VERSION 5.7 ;
  NOWIREEXTENSIONATPIN ON ;
  DIVIDERCHAR "/" ;
  BUSBITCHARS "[]" ;
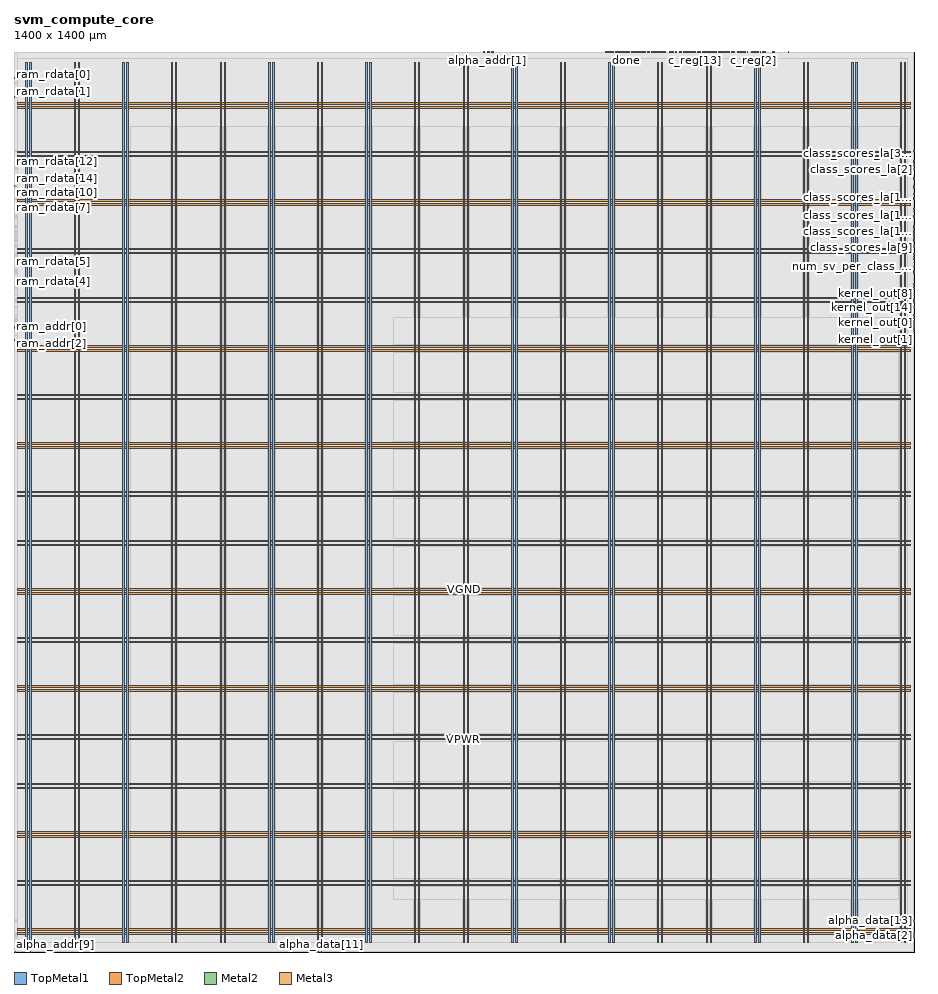
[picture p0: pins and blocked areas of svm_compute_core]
MACRO svm_compute_core
  CLASS BLOCK ;
  FOREIGN svm_compute_core ;
  ORIGIN 0.000 0.000 ;
  SIZE 1400.000 BY 1400.000 ;
  PIN VGND
    DIRECTION INOUT ;
    USE GROUND ;
    PORT
      LAYER TopMetal1 ;
        RECT 24.460 14.490 26.660 1384.110 ;
    END
    PORT
      LAYER TopMetal1 ;
        RECT 100.060 14.490 102.260 1384.110 ;
    END
    PORT
      LAYER TopMetal1 ;
        RECT 175.660 14.490 177.860 1384.110 ;
    END
    PORT
      LAYER TopMetal1 ;
        RECT 251.260 14.490 253.460 1384.110 ;
    END
    PORT
      LAYER TopMetal1 ;
        RECT 326.860 14.490 329.060 1384.110 ;
    END
    PORT
      LAYER TopMetal1 ;
        RECT 402.460 14.490 404.660 1384.110 ;
    END
    PORT
      LAYER TopMetal1 ;
        RECT 478.060 14.490 480.260 1384.110 ;
    END
    PORT
      LAYER TopMetal1 ;
        RECT 553.660 14.490 555.860 1384.110 ;
    END
    PORT
      LAYER TopMetal1 ;
        RECT 629.260 14.490 631.460 1384.110 ;
    END
    PORT
      LAYER TopMetal1 ;
        RECT 704.860 14.490 707.060 1384.110 ;
    END
    PORT
      LAYER TopMetal1 ;
        RECT 780.460 14.490 782.660 1384.110 ;
    END
    PORT
      LAYER TopMetal1 ;
        RECT 856.060 14.490 858.260 1384.110 ;
    END
    PORT
      LAYER TopMetal1 ;
        RECT 931.660 14.490 933.860 1384.110 ;
    END
    PORT
      LAYER TopMetal1 ;
        RECT 1007.260 14.490 1009.460 1384.110 ;
    END
    PORT
      LAYER TopMetal1 ;
        RECT 1082.860 14.490 1085.060 1384.110 ;
    END
    PORT
      LAYER TopMetal1 ;
        RECT 1158.460 14.490 1160.660 1384.110 ;
    END
    PORT
      LAYER TopMetal1 ;
        RECT 1234.060 14.490 1236.260 1384.110 ;
    END
    PORT
      LAYER TopMetal1 ;
        RECT 1309.660 14.490 1311.860 1384.110 ;
    END
    PORT
      LAYER TopMetal1 ;
        RECT 1385.260 14.490 1387.460 1384.110 ;
    END
    PORT
      LAYER TopMetal2 ;
        RECT 5.760 33.820 1393.920 36.020 ;
    END
    PORT
      LAYER TopMetal2 ;
        RECT 5.760 109.420 1393.920 111.620 ;
    END
    PORT
      LAYER TopMetal2 ;
        RECT 5.760 185.020 1393.920 187.220 ;
    END
    PORT
      LAYER TopMetal2 ;
        RECT 5.760 260.620 1393.920 262.820 ;
    END
    PORT
      LAYER TopMetal2 ;
        RECT 5.760 336.220 1393.920 338.420 ;
    END
    PORT
      LAYER TopMetal2 ;
        RECT 5.760 411.820 1393.920 414.020 ;
    END
    PORT
      LAYER TopMetal2 ;
        RECT 5.760 487.420 1393.920 489.620 ;
    END
    PORT
      LAYER TopMetal2 ;
        RECT 5.760 563.020 1393.920 565.220 ;
    END
    PORT
      LAYER TopMetal2 ;
        RECT 5.760 638.620 1393.920 640.820 ;
    END
    PORT
      LAYER TopMetal2 ;
        RECT 5.760 714.220 1393.920 716.420 ;
    END
    PORT
      LAYER TopMetal2 ;
        RECT 5.760 789.820 1393.920 792.020 ;
    END
    PORT
      LAYER TopMetal2 ;
        RECT 5.760 865.420 1393.920 867.620 ;
    END
    PORT
      LAYER TopMetal2 ;
        RECT 5.760 941.020 1393.920 943.220 ;
    END
    PORT
      LAYER TopMetal2 ;
        RECT 5.760 1016.620 1393.920 1018.820 ;
    END
    PORT
      LAYER TopMetal2 ;
        RECT 5.760 1092.220 1393.920 1094.420 ;
    END
    PORT
      LAYER TopMetal2 ;
        RECT 5.760 1167.820 1393.920 1170.020 ;
    END
    PORT
      LAYER TopMetal2 ;
        RECT 5.760 1243.420 1393.920 1245.620 ;
    END
    PORT
      LAYER TopMetal2 ;
        RECT 5.760 1319.020 1393.920 1321.220 ;
    END
  END VGND
  PIN VPWR
    DIRECTION INOUT ;
    USE POWER ;
    PORT
      LAYER TopMetal1 ;
        RECT 18.260 14.900 20.460 1383.700 ;
    END
    PORT
      LAYER TopMetal1 ;
        RECT 93.860 14.900 96.060 1383.700 ;
    END
    PORT
      LAYER TopMetal1 ;
        RECT 169.460 14.900 171.660 1383.700 ;
    END
    PORT
      LAYER TopMetal1 ;
        RECT 245.060 14.900 247.260 1383.700 ;
    END
    PORT
      LAYER TopMetal1 ;
        RECT 320.660 14.900 322.860 1383.700 ;
    END
    PORT
      LAYER TopMetal1 ;
        RECT 396.260 14.900 398.460 1383.700 ;
    END
    PORT
      LAYER TopMetal1 ;
        RECT 471.860 14.900 474.060 1383.700 ;
    END
    PORT
      LAYER TopMetal1 ;
        RECT 547.460 14.900 549.660 1383.700 ;
    END
    PORT
      LAYER TopMetal1 ;
        RECT 623.060 14.900 625.260 1383.700 ;
    END
    PORT
      LAYER TopMetal1 ;
        RECT 698.660 14.900 700.860 1383.700 ;
    END
    PORT
      LAYER TopMetal1 ;
        RECT 774.260 14.900 776.460 1383.700 ;
    END
    PORT
      LAYER TopMetal1 ;
        RECT 849.860 14.900 852.060 1383.700 ;
    END
    PORT
      LAYER TopMetal1 ;
        RECT 925.460 14.900 927.660 1383.700 ;
    END
    PORT
      LAYER TopMetal1 ;
        RECT 1001.060 14.900 1003.260 1383.700 ;
    END
    PORT
      LAYER TopMetal1 ;
        RECT 1076.660 14.900 1078.860 1383.700 ;
    END
    PORT
      LAYER TopMetal1 ;
        RECT 1152.260 14.900 1154.460 1383.700 ;
    END
    PORT
      LAYER TopMetal1 ;
        RECT 1227.860 14.900 1230.060 1383.700 ;
    END
    PORT
      LAYER TopMetal1 ;
        RECT 1303.460 14.900 1305.660 1383.700 ;
    END
    PORT
      LAYER TopMetal1 ;
        RECT 1379.060 14.900 1381.260 1383.700 ;
    END
    PORT
      LAYER TopMetal2 ;
        RECT 5.760 27.620 1393.920 29.820 ;
    END
    PORT
      LAYER TopMetal2 ;
        RECT 5.760 103.220 1393.920 105.420 ;
    END
    PORT
      LAYER TopMetal2 ;
        RECT 5.760 178.820 1393.920 181.020 ;
    END
    PORT
      LAYER TopMetal2 ;
        RECT 5.760 254.420 1393.920 256.620 ;
    END
    PORT
      LAYER TopMetal2 ;
        RECT 5.760 330.020 1393.920 332.220 ;
    END
    PORT
      LAYER TopMetal2 ;
        RECT 5.760 405.620 1393.920 407.820 ;
    END
    PORT
      LAYER TopMetal2 ;
        RECT 5.760 481.220 1393.920 483.420 ;
    END
    PORT
      LAYER TopMetal2 ;
        RECT 5.760 556.820 1393.920 559.020 ;
    END
    PORT
      LAYER TopMetal2 ;
        RECT 5.760 632.420 1393.920 634.620 ;
    END
    PORT
      LAYER TopMetal2 ;
        RECT 5.760 708.020 1393.920 710.220 ;
    END
    PORT
      LAYER TopMetal2 ;
        RECT 5.760 783.620 1393.920 785.820 ;
    END
    PORT
      LAYER TopMetal2 ;
        RECT 5.760 859.220 1393.920 861.420 ;
    END
    PORT
      LAYER TopMetal2 ;
        RECT 5.760 934.820 1393.920 937.020 ;
    END
    PORT
      LAYER TopMetal2 ;
        RECT 5.760 1010.420 1393.920 1012.620 ;
    END
    PORT
      LAYER TopMetal2 ;
        RECT 5.760 1086.020 1393.920 1088.220 ;
    END
    PORT
      LAYER TopMetal2 ;
        RECT 5.760 1161.620 1393.920 1163.820 ;
    END
    PORT
      LAYER TopMetal2 ;
        RECT 5.760 1237.220 1393.920 1239.420 ;
    END
    PORT
      LAYER TopMetal2 ;
        RECT 5.760 1312.820 1393.920 1315.020 ;
    END
  END VPWR
  PIN alpha_addr[0]
    DIRECTION INPUT ;
    USE SIGNAL ;
    ANTENNAGATEAREA 0.109200 ;
    PORT
      LAYER Metal2 ;
        RECT 737.560 1399.600 737.960 1400.000 ;
    END
  END alpha_addr[0]
  PIN alpha_addr[1]
    DIRECTION INPUT ;
    USE SIGNAL ;
    ANTENNAGATEAREA 0.109200 ;
    PORT
      LAYER Metal2 ;
        RECT 736.600 1399.600 737.000 1400.000 ;
    END
  END alpha_addr[1]
  PIN alpha_addr[2]
    DIRECTION INPUT ;
    USE SIGNAL ;
    ANTENNAGATEAREA 0.109200 ;
    PORT
      LAYER Metal2 ;
        RECT 745.240 1399.600 745.640 1400.000 ;
    END
  END alpha_addr[2]
  PIN alpha_addr[3]
    DIRECTION INPUT ;
    USE SIGNAL ;
    ANTENNAGATEAREA 0.109200 ;
    PORT
      LAYER Metal2 ;
        RECT 746.200 1399.600 746.600 1400.000 ;
    END
  END alpha_addr[3]
  PIN alpha_addr[4]
    DIRECTION INPUT ;
    USE SIGNAL ;
    ANTENNAGATEAREA 0.109200 ;
    PORT
      LAYER Metal2 ;
        RECT 738.520 1399.600 738.920 1400.000 ;
    END
  END alpha_addr[4]
  PIN alpha_addr[5]
    DIRECTION INPUT ;
    USE SIGNAL ;
    ANTENNAGATEAREA 0.109200 ;
    PORT
      LAYER Metal2 ;
        RECT 739.480 1399.600 739.880 1400.000 ;
    END
  END alpha_addr[5]
  PIN alpha_addr[6]
    DIRECTION INPUT ;
    USE SIGNAL ;
    ANTENNAGATEAREA 0.109200 ;
    PORT
      LAYER Metal2 ;
        RECT 744.280 1399.600 744.680 1400.000 ;
    END
  END alpha_addr[6]
  PIN alpha_addr[7]
    DIRECTION INPUT ;
    USE SIGNAL ;
    ANTENNAGATEAREA 0.109200 ;
    PORT
      LAYER Metal2 ;
        RECT 743.320 1399.600 743.720 1400.000 ;
    END
  END alpha_addr[7]
  PIN alpha_addr[8]
    DIRECTION INPUT ;
    USE SIGNAL ;
    ANTENNAGATEAREA 0.109200 ;
    PORT
      LAYER Metal2 ;
        RECT 730.840 1399.600 731.240 1400.000 ;
    END
  END alpha_addr[8]
  PIN alpha_addr[9]
    DIRECTION INPUT ;
    USE SIGNAL ;
    PORT
      LAYER Metal2 ;
        RECT 2.200 0.000 2.600 0.400 ;
    END
  END alpha_addr[9]
  PIN alpha_data[0]
    DIRECTION INPUT ;
    USE SIGNAL ;
    ANTENNAGATEAREA 0.109200 ;
    PORT
      LAYER Metal2 ;
        RECT 996.760 1399.600 997.160 1400.000 ;
    END
  END alpha_data[0]
  PIN alpha_data[10]
    DIRECTION INPUT ;
    USE SIGNAL ;
    ANTENNAGATEAREA 0.109200 ;
    PORT
      LAYER Metal2 ;
        RECT 1012.120 1399.600 1012.520 1400.000 ;
    END
  END alpha_data[10]
  PIN alpha_data[11]
    DIRECTION INPUT ;
    USE SIGNAL ;
    ANTENNAGATEAREA 0.109200 ;
    PORT
      LAYER Metal2 ;
        RECT 478.360 0.000 478.760 0.400 ;
    END
  END alpha_data[11]
  PIN alpha_data[12]
    DIRECTION INPUT ;
    USE SIGNAL ;
    ANTENNAGATEAREA 0.109200 ;
    PORT
      LAYER Metal2 ;
        RECT 472.600 0.000 473.000 0.400 ;
    END
  END alpha_data[12]
  PIN alpha_data[13]
    DIRECTION INPUT ;
    USE SIGNAL ;
    ANTENNAGATEAREA 0.109200 ;
    PORT
      LAYER Metal3 ;
        RECT 1399.600 48.100 1400.000 48.500 ;
    END
  END alpha_data[13]
  PIN alpha_data[14]
    DIRECTION INPUT ;
    USE SIGNAL ;
    ANTENNAGATEAREA 0.109200 ;
    PORT
      LAYER Metal3 ;
        RECT 1399.600 22.900 1400.000 23.300 ;
    END
  END alpha_data[14]
  PIN alpha_data[15]
    DIRECTION INPUT ;
    USE SIGNAL ;
    ANTENNAGATEAREA 0.109200 ;
    PORT
      LAYER Metal3 ;
        RECT 1399.600 23.740 1400.000 24.140 ;
    END
  END alpha_data[15]
  PIN alpha_data[1]
    DIRECTION INPUT ;
    USE SIGNAL ;
    ANTENNAGATEAREA 0.109200 ;
    PORT
      LAYER Metal3 ;
        RECT 1399.600 24.580 1400.000 24.980 ;
    END
  END alpha_data[1]
  PIN alpha_data[2]
    DIRECTION INPUT ;
    USE SIGNAL ;
    ANTENNAGATEAREA 0.109200 ;
    PORT
      LAYER Metal3 ;
        RECT 1399.600 25.420 1400.000 25.820 ;
    END
  END alpha_data[2]
  PIN alpha_data[3]
    DIRECTION INPUT ;
    USE SIGNAL ;
    ANTENNAGATEAREA 0.109200 ;
    PORT
      LAYER Metal3 ;
        RECT 1399.600 26.260 1400.000 26.660 ;
    END
  END alpha_data[3]
  PIN alpha_data[4]
    DIRECTION INPUT ;
    USE SIGNAL ;
    ANTENNAGATEAREA 0.109200 ;
    PORT
      LAYER Metal2 ;
        RECT 1205.080 1399.600 1205.480 1400.000 ;
    END
  END alpha_data[4]
  PIN alpha_data[5]
    DIRECTION INPUT ;
    USE SIGNAL ;
    ANTENNAGATEAREA 0.109200 ;
    PORT
      LAYER Metal3 ;
        RECT 1399.600 27.100 1400.000 27.500 ;
    END
  END alpha_data[5]
  PIN alpha_data[6]
    DIRECTION INPUT ;
    USE SIGNAL ;
    ANTENNAGATEAREA 0.109200 ;
    PORT
      LAYER Metal3 ;
        RECT 1399.600 27.940 1400.000 28.340 ;
    END
  END alpha_data[6]
  PIN alpha_data[7]
    DIRECTION INPUT ;
    USE SIGNAL ;
    ANTENNAGATEAREA 0.109200 ;
    PORT
      LAYER Metal3 ;
        RECT 1399.600 49.780 1400.000 50.180 ;
    END
  END alpha_data[7]
  PIN alpha_data[8]
    DIRECTION INPUT ;
    USE SIGNAL ;
    ANTENNAGATEAREA 0.109200 ;
    PORT
      LAYER Metal3 ;
        RECT 1399.600 48.940 1400.000 49.340 ;
    END
  END alpha_data[8]
  PIN alpha_data[9]
    DIRECTION INPUT ;
    USE SIGNAL ;
    ANTENNAGATEAREA 0.109200 ;
    PORT
      LAYER Metal3 ;
        RECT 1399.600 28.780 1400.000 29.180 ;
    END
  END alpha_data[9]
  PIN alpha_write_en
    DIRECTION INPUT ;
    USE SIGNAL ;
    ANTENNAGATEAREA 0.109200 ;
    PORT
      LAYER Metal2 ;
        RECT 729.880 1399.600 730.280 1400.000 ;
    END
  END alpha_write_en
  PIN c_reg[0]
    DIRECTION OUTPUT ;
    USE SIGNAL ;
    ANTENNADIFFAREA 0.708600 ;
    PORT
      LAYER Metal2 ;
        RECT 1133.080 1399.600 1133.480 1400.000 ;
    END
  END c_reg[0]
  PIN c_reg[10]
    DIRECTION OUTPUT ;
    USE SIGNAL ;
    ANTENNADIFFAREA 0.708600 ;
    PORT
      LAYER Metal2 ;
        RECT 1126.360 1399.600 1126.760 1400.000 ;
    END
  END c_reg[10]
  PIN c_reg[11]
    DIRECTION OUTPUT ;
    USE SIGNAL ;
    ANTENNADIFFAREA 0.708600 ;
    PORT
      LAYER Metal2 ;
        RECT 1102.360 1399.600 1102.760 1400.000 ;
    END
  END c_reg[11]
  PIN c_reg[12]
    DIRECTION OUTPUT ;
    USE SIGNAL ;
    ANTENNADIFFAREA 0.708600 ;
    PORT
      LAYER Metal2 ;
        RECT 1091.800 1399.600 1092.200 1400.000 ;
    END
  END c_reg[12]
  PIN c_reg[13]
    DIRECTION OUTPUT ;
    USE SIGNAL ;
    ANTENNADIFFAREA 0.708600 ;
    PORT
      LAYER Metal2 ;
        RECT 1059.160 1399.600 1059.560 1400.000 ;
    END
  END c_reg[13]
  PIN c_reg[14]
    DIRECTION OUTPUT ;
    USE SIGNAL ;
    ANTENNADIFFAREA 0.708600 ;
    PORT
      LAYER Metal2 ;
        RECT 1054.360 1399.600 1054.760 1400.000 ;
    END
  END c_reg[14]
  PIN c_reg[15]
    DIRECTION OUTPUT ;
    USE SIGNAL ;
    ANTENNADIFFAREA 0.708600 ;
    PORT
      LAYER Metal2 ;
        RECT 1078.360 1399.600 1078.760 1400.000 ;
    END
  END c_reg[15]
  PIN c_reg[1]
    DIRECTION OUTPUT ;
    USE SIGNAL ;
    ANTENNADIFFAREA 0.708600 ;
    PORT
      LAYER Metal2 ;
        RECT 1134.040 1399.600 1134.440 1400.000 ;
    END
  END c_reg[1]
  PIN c_reg[2]
    DIRECTION OUTPUT ;
    USE SIGNAL ;
    ANTENNADIFFAREA 0.708600 ;
    PORT
      LAYER Metal2 ;
        RECT 1149.400 1399.600 1149.800 1400.000 ;
    END
  END c_reg[2]
  PIN c_reg[3]
    DIRECTION OUTPUT ;
    USE SIGNAL ;
    ANTENNADIFFAREA 0.708600 ;
    PORT
      LAYER Metal2 ;
        RECT 1136.920 1399.600 1137.320 1400.000 ;
    END
  END c_reg[3]
  PIN c_reg[4]
    DIRECTION OUTPUT ;
    USE SIGNAL ;
    ANTENNADIFFAREA 0.708600 ;
    PORT
      LAYER Metal2 ;
        RECT 1154.200 1399.600 1154.600 1400.000 ;
    END
  END c_reg[4]
  PIN c_reg[5]
    DIRECTION OUTPUT ;
    USE SIGNAL ;
    ANTENNADIFFAREA 0.708600 ;
    PORT
      LAYER Metal2 ;
        RECT 1156.120 1399.600 1156.520 1400.000 ;
    END
  END c_reg[5]
  PIN c_reg[6]
    DIRECTION OUTPUT ;
    USE SIGNAL ;
    ANTENNADIFFAREA 0.708600 ;
    PORT
      LAYER Metal2 ;
        RECT 1155.160 1399.600 1155.560 1400.000 ;
    END
  END c_reg[6]
  PIN c_reg[7]
    DIRECTION OUTPUT ;
    USE SIGNAL ;
    ANTENNADIFFAREA 0.708600 ;
    PORT
      LAYER Metal2 ;
        RECT 1148.440 1399.600 1148.840 1400.000 ;
    END
  END c_reg[7]
  PIN c_reg[8]
    DIRECTION OUTPUT ;
    USE SIGNAL ;
    ANTENNADIFFAREA 0.708600 ;
    PORT
      LAYER Metal2 ;
        RECT 1098.520 1399.600 1098.920 1400.000 ;
    END
  END c_reg[8]
  PIN c_reg[9]
    DIRECTION OUTPUT ;
    USE SIGNAL ;
    ANTENNADIFFAREA 0.708600 ;
    PORT
      LAYER Metal2 ;
        RECT 1119.640 1399.600 1120.040 1400.000 ;
    END
  END c_reg[9]
  PIN class_out[0]
    DIRECTION OUTPUT ;
    USE SIGNAL ;
    ANTENNADIFFAREA 0.708600 ;
    PORT
      LAYER Metal2 ;
        RECT 1111.960 1399.600 1112.360 1400.000 ;
    END
  END class_out[0]
  PIN class_out[1]
    DIRECTION OUTPUT ;
    USE SIGNAL ;
    ANTENNADIFFAREA 0.708600 ;
    PORT
      LAYER Metal2 ;
        RECT 1111.000 1399.600 1111.400 1400.000 ;
    END
  END class_out[1]
  PIN class_out[2]
    DIRECTION OUTPUT ;
    USE SIGNAL ;
    ANTENNADIFFAREA 0.708600 ;
    PORT
      LAYER Metal2 ;
        RECT 1110.040 1399.600 1110.440 1400.000 ;
    END
  END class_out[2]
  PIN class_scores_la[0]
    DIRECTION OUTPUT ;
    USE SIGNAL ;
    ANTENNADIFFAREA 0.708600 ;
    PORT
      LAYER Metal3 ;
        RECT 1399.600 1219.060 1400.000 1219.460 ;
    END
  END class_scores_la[0]
  PIN class_scores_la[100]
    DIRECTION OUTPUT ;
    USE SIGNAL ;
    ANTENNADIFFAREA 0.708600 ;
    PORT
      LAYER Metal3 ;
        RECT 1399.600 1173.700 1400.000 1174.100 ;
    END
  END class_scores_la[100]
  PIN class_scores_la[101]
    DIRECTION OUTPUT ;
    USE SIGNAL ;
    ANTENNADIFFAREA 0.708600 ;
    PORT
      LAYER Metal3 ;
        RECT 1399.600 1156.060 1400.000 1156.460 ;
    END
  END class_scores_la[101]
  PIN class_scores_la[102]
    DIRECTION OUTPUT ;
    USE SIGNAL ;
    ANTENNADIFFAREA 0.708600 ;
    PORT
      LAYER Metal3 ;
        RECT 1399.600 1141.780 1400.000 1142.180 ;
    END
  END class_scores_la[102]
  PIN class_scores_la[103]
    DIRECTION OUTPUT ;
    USE SIGNAL ;
    ANTENNADIFFAREA 0.708600 ;
    PORT
      LAYER Metal3 ;
        RECT 1399.600 1119.940 1400.000 1120.340 ;
    END
  END class_scores_la[103]
  PIN class_scores_la[104]
    DIRECTION OUTPUT ;
    USE SIGNAL ;
    ANTENNADIFFAREA 0.708600 ;
    PORT
      LAYER Metal3 ;
        RECT 1399.600 1145.140 1400.000 1145.540 ;
    END
  END class_scores_la[104]
  PIN class_scores_la[105]
    DIRECTION OUTPUT ;
    USE SIGNAL ;
    ANTENNADIFFAREA 0.708600 ;
    PORT
      LAYER Metal2 ;
        RECT 1164.760 1399.600 1165.160 1400.000 ;
    END
  END class_scores_la[105]
  PIN class_scores_la[106]
    DIRECTION OUTPUT ;
    USE SIGNAL ;
    ANTENNADIFFAREA 0.708600 ;
    PORT
      LAYER Metal2 ;
        RECT 1147.480 1399.600 1147.880 1400.000 ;
    END
  END class_scores_la[106]
  PIN class_scores_la[107]
    DIRECTION OUTPUT ;
    USE SIGNAL ;
    ANTENNADIFFAREA 0.708600 ;
    PORT
      LAYER Metal2 ;
        RECT 1135.960 1399.600 1136.360 1400.000 ;
    END
  END class_scores_la[107]
  PIN class_scores_la[108]
    DIRECTION OUTPUT ;
    USE SIGNAL ;
    ANTENNADIFFAREA 0.708600 ;
    PORT
      LAYER Metal2 ;
        RECT 1117.720 1399.600 1118.120 1400.000 ;
    END
  END class_scores_la[108]
  PIN class_scores_la[109]
    DIRECTION OUTPUT ;
    USE SIGNAL ;
    ANTENNADIFFAREA 0.708600 ;
    PORT
      LAYER Metal2 ;
        RECT 1104.280 1399.600 1104.680 1400.000 ;
    END
  END class_scores_la[109]
  PIN class_scores_la[10]
    DIRECTION OUTPUT ;
    USE SIGNAL ;
    ANTENNADIFFAREA 0.708600 ;
    PORT
      LAYER Metal2 ;
        RECT 1168.600 1399.600 1169.000 1400.000 ;
    END
  END class_scores_la[10]
  PIN class_scores_la[110]
    DIRECTION OUTPUT ;
    USE SIGNAL ;
    ANTENNADIFFAREA 0.708600 ;
    PORT
      LAYER Metal2 ;
        RECT 1099.480 1399.600 1099.880 1400.000 ;
    END
  END class_scores_la[110]
  PIN class_scores_la[111]
    DIRECTION OUTPUT ;
    USE SIGNAL ;
    ANTENNADIFFAREA 0.708600 ;
    PORT
      LAYER Metal2 ;
        RECT 1097.560 1399.600 1097.960 1400.000 ;
    END
  END class_scores_la[111]
  PIN class_scores_la[112]
    DIRECTION OUTPUT ;
    USE SIGNAL ;
    ANTENNADIFFAREA 0.708600 ;
    PORT
      LAYER Metal2 ;
        RECT 1025.560 1399.600 1025.960 1400.000 ;
    END
  END class_scores_la[112]
  PIN class_scores_la[113]
    DIRECTION OUTPUT ;
    USE SIGNAL ;
    ANTENNADIFFAREA 0.708600 ;
    PORT
      LAYER Metal2 ;
        RECT 1011.160 1399.600 1011.560 1400.000 ;
    END
  END class_scores_la[113]
  PIN class_scores_la[114]
    DIRECTION OUTPUT ;
    USE SIGNAL ;
    ANTENNADIFFAREA 0.708600 ;
    PORT
      LAYER Metal2 ;
        RECT 992.920 1399.600 993.320 1400.000 ;
    END
  END class_scores_la[114]
  PIN class_scores_la[115]
    DIRECTION OUTPUT ;
    USE SIGNAL ;
    ANTENNADIFFAREA 0.708600 ;
    PORT
      LAYER Metal2 ;
        RECT 988.120 1399.600 988.520 1400.000 ;
    END
  END class_scores_la[115]
  PIN class_scores_la[116]
    DIRECTION OUTPUT ;
    USE SIGNAL ;
    ANTENNADIFFAREA 0.708600 ;
    PORT
      LAYER Metal2 ;
        RECT 968.920 1399.600 969.320 1400.000 ;
    END
  END class_scores_la[116]
  PIN class_scores_la[117]
    DIRECTION OUTPUT ;
    USE SIGNAL ;
    ANTENNADIFFAREA 0.708600 ;
    PORT
      LAYER Metal2 ;
        RECT 994.840 1399.600 995.240 1400.000 ;
    END
  END class_scores_la[117]
  PIN class_scores_la[118]
    DIRECTION OUTPUT ;
    USE SIGNAL ;
    ANTENNADIFFAREA 0.708600 ;
    PORT
      LAYER Metal2 ;
        RECT 995.800 1399.600 996.200 1400.000 ;
    END
  END class_scores_la[118]
  PIN class_scores_la[119]
    DIRECTION OUTPUT ;
    USE SIGNAL ;
    ANTENNADIFFAREA 0.708600 ;
    PORT
      LAYER Metal2 ;
        RECT 1046.680 1399.600 1047.080 1400.000 ;
    END
  END class_scores_la[119]
  PIN class_scores_la[11]
    DIRECTION OUTPUT ;
    USE SIGNAL ;
    ANTENNADIFFAREA 0.708600 ;
    PORT
      LAYER Metal2 ;
        RECT 1130.200 1399.600 1130.600 1400.000 ;
    END
  END class_scores_la[11]
  PIN class_scores_la[120]
    DIRECTION OUTPUT ;
    USE SIGNAL ;
    ANTENNADIFFAREA 0.708600 ;
    PORT
      LAYER Metal2 ;
        RECT 1006.360 1399.600 1006.760 1400.000 ;
    END
  END class_scores_la[120]
  PIN class_scores_la[121]
    DIRECTION OUTPUT ;
    USE SIGNAL ;
    ANTENNADIFFAREA 0.708600 ;
    PORT
      LAYER Metal2 ;
        RECT 998.680 1399.600 999.080 1400.000 ;
    END
  END class_scores_la[121]
  PIN class_scores_la[122]
    DIRECTION OUTPUT ;
    USE SIGNAL ;
    ANTENNADIFFAREA 0.708600 ;
    PORT
      LAYER Metal2 ;
        RECT 976.600 1399.600 977.000 1400.000 ;
    END
  END class_scores_la[122]
  PIN class_scores_la[123]
    DIRECTION OUTPUT ;
    USE SIGNAL ;
    ANTENNADIFFAREA 0.708600 ;
    PORT
      LAYER Metal2 ;
        RECT 966.040 1399.600 966.440 1400.000 ;
    END
  END class_scores_la[123]
  PIN class_scores_la[124]
    DIRECTION OUTPUT ;
    USE SIGNAL ;
    ANTENNADIFFAREA 0.708600 ;
    PORT
      LAYER Metal2 ;
        RECT 1088.920 1399.600 1089.320 1400.000 ;
    END
  END class_scores_la[124]
  PIN class_scores_la[125]
    DIRECTION OUTPUT ;
    USE SIGNAL ;
    ANTENNADIFFAREA 0.708600 ;
    PORT
      LAYER Metal2 ;
        RECT 1075.480 1399.600 1075.880 1400.000 ;
    END
  END class_scores_la[125]
  PIN class_scores_la[126]
    DIRECTION OUTPUT ;
    USE SIGNAL ;
    ANTENNADIFFAREA 0.708600 ;
    PORT
      LAYER Metal2 ;
        RECT 1077.400 1399.600 1077.800 1400.000 ;
    END
  END class_scores_la[126]
  PIN class_scores_la[127]
    DIRECTION OUTPUT ;
    USE SIGNAL ;
    ANTENNADIFFAREA 0.708600 ;
    PORT
      LAYER Metal2 ;
        RECT 1085.080 1399.600 1085.480 1400.000 ;
    END
  END class_scores_la[127]
  PIN class_scores_la[12]
    DIRECTION OUTPUT ;
    USE SIGNAL ;
    ANTENNADIFFAREA 0.708600 ;
    PORT
      LAYER Metal3 ;
        RECT 1399.600 1104.820 1400.000 1105.220 ;
    END
  END class_scores_la[12]
  PIN class_scores_la[13]
    DIRECTION OUTPUT ;
    USE SIGNAL ;
    ANTENNADIFFAREA 0.708600 ;
    PORT
      LAYER Metal2 ;
        RECT 1100.440 1399.600 1100.840 1400.000 ;
    END
  END class_scores_la[13]
  PIN class_scores_la[14]
    DIRECTION OUTPUT ;
    USE SIGNAL ;
    ANTENNADIFFAREA 0.708600 ;
    PORT
      LAYER Metal2 ;
        RECT 1086.040 1399.600 1086.440 1400.000 ;
    END
  END class_scores_la[14]
  PIN class_scores_la[15]
    DIRECTION OUTPUT ;
    USE SIGNAL ;
    ANTENNADIFFAREA 0.708600 ;
    PORT
      LAYER Metal2 ;
        RECT 1081.240 1399.600 1081.640 1400.000 ;
    END
  END class_scores_la[15]
  PIN class_scores_la[16]
    DIRECTION OUTPUT ;
    USE SIGNAL ;
    ANTENNADIFFAREA 0.708600 ;
    PORT
      LAYER Metal2 ;
        RECT 1055.320 1399.600 1055.720 1400.000 ;
    END
  END class_scores_la[16]
  PIN class_scores_la[17]
    DIRECTION OUTPUT ;
    USE SIGNAL ;
    ANTENNADIFFAREA 0.708600 ;
    PORT
      LAYER Metal2 ;
        RECT 1045.720 1399.600 1046.120 1400.000 ;
    END
  END class_scores_la[17]
  PIN class_scores_la[18]
    DIRECTION OUTPUT ;
    USE SIGNAL ;
    ANTENNADIFFAREA 0.708600 ;
    PORT
      LAYER Metal2 ;
        RECT 1023.640 1399.600 1024.040 1400.000 ;
    END
  END class_scores_la[18]
  PIN class_scores_la[19]
    DIRECTION OUTPUT ;
    USE SIGNAL ;
    ANTENNADIFFAREA 0.708600 ;
    PORT
      LAYER Metal2 ;
        RECT 1009.240 1399.600 1009.640 1400.000 ;
    END
  END class_scores_la[19]
  PIN class_scores_la[1]
    DIRECTION OUTPUT ;
    USE SIGNAL ;
    ANTENNADIFFAREA 0.708600 ;
    PORT
      LAYER Metal3 ;
        RECT 1399.600 1224.100 1400.000 1224.500 ;
    END
  END class_scores_la[1]
  PIN class_scores_la[20]
    DIRECTION OUTPUT ;
    USE SIGNAL ;
    ANTENNADIFFAREA 0.708600 ;
    PORT
      LAYER Metal2 ;
        RECT 969.880 1399.600 970.280 1400.000 ;
    END
  END class_scores_la[20]
  PIN class_scores_la[21]
    DIRECTION OUTPUT ;
    USE SIGNAL ;
    ANTENNADIFFAREA 0.708600 ;
    PORT
      LAYER Metal2 ;
        RECT 981.400 1399.600 981.800 1400.000 ;
    END
  END class_scores_la[21]
  PIN class_scores_la[22]
    DIRECTION OUTPUT ;
    USE SIGNAL ;
    ANTENNADIFFAREA 0.708600 ;
    PORT
      LAYER Metal2 ;
        RECT 1029.400 1399.600 1029.800 1400.000 ;
    END
  END class_scores_la[22]
  PIN class_scores_la[23]
    DIRECTION OUTPUT ;
    USE SIGNAL ;
    ANTENNADIFFAREA 0.708600 ;
    PORT
      LAYER Metal2 ;
        RECT 1053.400 1399.600 1053.800 1400.000 ;
    END
  END class_scores_la[23]
  PIN class_scores_la[24]
    DIRECTION OUTPUT ;
    USE SIGNAL ;
    ANTENNADIFFAREA 0.708600 ;
    PORT
      LAYER Metal2 ;
        RECT 1021.720 1399.600 1022.120 1400.000 ;
    END
  END class_scores_la[24]
  PIN class_scores_la[25]
    DIRECTION OUTPUT ;
    USE SIGNAL ;
    ANTENNADIFFAREA 0.708600 ;
    PORT
      LAYER Metal2 ;
        RECT 1000.600 1399.600 1001.000 1400.000 ;
    END
  END class_scores_la[25]
  PIN class_scores_la[26]
    DIRECTION OUTPUT ;
    USE SIGNAL ;
    ANTENNADIFFAREA 0.708600 ;
    PORT
      LAYER Metal2 ;
        RECT 980.440 1399.600 980.840 1400.000 ;
    END
  END class_scores_la[26]
  PIN class_scores_la[27]
    DIRECTION OUTPUT ;
    USE SIGNAL ;
    ANTENNADIFFAREA 0.708600 ;
    PORT
      LAYER Metal2 ;
        RECT 970.840 1399.600 971.240 1400.000 ;
    END
  END class_scores_la[27]
  PIN class_scores_la[28]
    DIRECTION OUTPUT ;
    USE SIGNAL ;
    ANTENNADIFFAREA 0.708600 ;
    PORT
      LAYER Metal2 ;
        RECT 1038.040 1399.600 1038.440 1400.000 ;
    END
  END class_scores_la[28]
  PIN class_scores_la[29]
    DIRECTION OUTPUT ;
    USE SIGNAL ;
    ANTENNADIFFAREA 0.708600 ;
    PORT
      LAYER Metal2 ;
        RECT 1052.440 1399.600 1052.840 1400.000 ;
    END
  END class_scores_la[29]
  PIN class_scores_la[2]
    DIRECTION OUTPUT ;
    USE SIGNAL ;
    ANTENNADIFFAREA 0.708600 ;
    PORT
      LAYER Metal3 ;
        RECT 1399.600 1217.380 1400.000 1217.780 ;
    END
  END class_scores_la[2]
  PIN class_scores_la[30]
    DIRECTION OUTPUT ;
    USE SIGNAL ;
    ANTENNADIFFAREA 0.708600 ;
    PORT
      LAYER Metal2 ;
        RECT 1044.760 1399.600 1045.160 1400.000 ;
    END
  END class_scores_la[30]
  PIN class_scores_la[31]
    DIRECTION OUTPUT ;
    USE SIGNAL ;
    ANTENNADIFFAREA 0.708600 ;
    PORT
      LAYER Metal2 ;
        RECT 1066.840 1399.600 1067.240 1400.000 ;
    END
  END class_scores_la[31]
  PIN class_scores_la[32]
    DIRECTION OUTPUT ;
    USE SIGNAL ;
    ANTENNADIFFAREA 0.708600 ;
    PORT
      LAYER Metal3 ;
        RECT 1399.600 1229.140 1400.000 1229.540 ;
    END
  END class_scores_la[32]
  PIN class_scores_la[33]
    DIRECTION OUTPUT ;
    USE SIGNAL ;
    ANTENNADIFFAREA 0.708600 ;
    PORT
      LAYER Metal3 ;
        RECT 1399.600 1229.980 1400.000 1230.380 ;
    END
  END class_scores_la[33]
  PIN class_scores_la[34]
    DIRECTION OUTPUT ;
    USE SIGNAL ;
    ANTENNADIFFAREA 0.708600 ;
    PORT
      LAYER Metal3 ;
        RECT 1399.600 1190.500 1400.000 1190.900 ;
    END
  END class_scores_la[34]
  PIN class_scores_la[35]
    DIRECTION OUTPUT ;
    USE SIGNAL ;
    ANTENNADIFFAREA 0.708600 ;
    PORT
      LAYER Metal3 ;
        RECT 1399.600 1188.820 1400.000 1189.220 ;
    END
  END class_scores_la[35]
  PIN class_scores_la[36]
    DIRECTION OUTPUT ;
    USE SIGNAL ;
    ANTENNADIFFAREA 0.708600 ;
    PORT
      LAYER Metal3 ;
        RECT 1399.600 1171.180 1400.000 1171.580 ;
    END
  END class_scores_la[36]
  PIN class_scores_la[37]
    DIRECTION OUTPUT ;
    USE SIGNAL ;
    ANTENNADIFFAREA 0.708600 ;
    PORT
      LAYER Metal3 ;
        RECT 1399.600 1151.860 1400.000 1152.260 ;
    END
  END class_scores_la[37]
  PIN class_scores_la[38]
    DIRECTION OUTPUT ;
    USE SIGNAL ;
    ANTENNADIFFAREA 0.708600 ;
    PORT
      LAYER Metal3 ;
        RECT 1399.600 1113.220 1400.000 1113.620 ;
    END
  END class_scores_la[38]
  PIN class_scores_la[39]
    DIRECTION OUTPUT ;
    USE SIGNAL ;
    ANTENNADIFFAREA 0.708600 ;
    PORT
      LAYER Metal3 ;
        RECT 1399.600 1129.180 1400.000 1129.580 ;
    END
  END class_scores_la[39]
  PIN class_scores_la[3]
    DIRECTION OUTPUT ;
    USE SIGNAL ;
    ANTENNADIFFAREA 0.708600 ;
    PORT
      LAYER Metal3 ;
        RECT 1399.600 1177.900 1400.000 1178.300 ;
    END
  END class_scores_la[3]
  PIN class_scores_la[40]
    DIRECTION OUTPUT ;
    USE SIGNAL ;
    ANTENNADIFFAREA 0.708600 ;
    PORT
      LAYER Metal3 ;
        RECT 1399.600 1121.620 1400.000 1122.020 ;
    END
  END class_scores_la[40]
  PIN class_scores_la[41]
    DIRECTION OUTPUT ;
    USE SIGNAL ;
    ANTENNADIFFAREA 0.708600 ;
    PORT
      LAYER Metal3 ;
        RECT 1399.600 1114.900 1400.000 1115.300 ;
    END
  END class_scores_la[41]
  PIN class_scores_la[42]
    DIRECTION OUTPUT ;
    USE SIGNAL ;
    ANTENNADIFFAREA 0.708600 ;
    PORT
      LAYER Metal2 ;
        RECT 1165.720 1399.600 1166.120 1400.000 ;
    END
  END class_scores_la[42]
  PIN class_scores_la[43]
    DIRECTION OUTPUT ;
    USE SIGNAL ;
    ANTENNADIFFAREA 0.708600 ;
    PORT
      LAYER Metal2 ;
        RECT 1132.120 1399.600 1132.520 1400.000 ;
    END
  END class_scores_la[43]
  PIN class_scores_la[44]
    DIRECTION OUTPUT ;
    USE SIGNAL ;
    ANTENNADIFFAREA 0.708600 ;
    PORT
      LAYER Metal3 ;
        RECT 1399.600 1106.500 1400.000 1106.900 ;
    END
  END class_scores_la[44]
  PIN class_scores_la[45]
    DIRECTION OUTPUT ;
    USE SIGNAL ;
    ANTENNADIFFAREA 0.708600 ;
    PORT
      LAYER Metal2 ;
        RECT 1125.400 1399.600 1125.800 1400.000 ;
    END
  END class_scores_la[45]
  PIN class_scores_la[46]
    DIRECTION OUTPUT ;
    USE SIGNAL ;
    ANTENNADIFFAREA 0.708600 ;
    PORT
      LAYER Metal2 ;
        RECT 1087.000 1399.600 1087.400 1400.000 ;
    END
  END class_scores_la[46]
  PIN class_scores_la[47]
    DIRECTION OUTPUT ;
    USE SIGNAL ;
    ANTENNADIFFAREA 0.708600 ;
    PORT
      LAYER Metal2 ;
        RECT 1084.120 1399.600 1084.520 1400.000 ;
    END
  END class_scores_la[47]
  PIN class_scores_la[48]
    DIRECTION OUTPUT ;
    USE SIGNAL ;
    ANTENNADIFFAREA 0.708600 ;
    PORT
      LAYER Metal2 ;
        RECT 1056.280 1399.600 1056.680 1400.000 ;
    END
  END class_scores_la[48]
  PIN class_scores_la[49]
    DIRECTION OUTPUT ;
    USE SIGNAL ;
    ANTENNADIFFAREA 0.708600 ;
    PORT
      LAYER Metal2 ;
        RECT 1041.880 1399.600 1042.280 1400.000 ;
    END
  END class_scores_la[49]
  PIN class_scores_la[4]
    DIRECTION OUTPUT ;
    USE SIGNAL ;
    ANTENNADIFFAREA 0.708600 ;
    PORT
      LAYER Metal3 ;
        RECT 1399.600 1170.340 1400.000 1170.740 ;
    END
  END class_scores_la[4]
  PIN class_scores_la[50]
    DIRECTION OUTPUT ;
    USE SIGNAL ;
    ANTENNADIFFAREA 0.708600 ;
    PORT
      LAYER Metal2 ;
        RECT 1030.360 1399.600 1030.760 1400.000 ;
    END
  END class_scores_la[50]
  PIN class_scores_la[51]
    DIRECTION OUTPUT ;
    USE SIGNAL ;
    ANTENNADIFFAREA 0.708600 ;
    PORT
      LAYER Metal2 ;
        RECT 997.720 1399.600 998.120 1400.000 ;
    END
  END class_scores_la[51]
  PIN class_scores_la[52]
    DIRECTION OUTPUT ;
    USE SIGNAL ;
    ANTENNADIFFAREA 0.708600 ;
    PORT
      LAYER Metal2 ;
        RECT 964.120 1399.600 964.520 1400.000 ;
    END
  END class_scores_la[52]
  PIN class_scores_la[53]
    DIRECTION OUTPUT ;
    USE SIGNAL ;
    ANTENNADIFFAREA 0.708600 ;
    PORT
      LAYER Metal2 ;
        RECT 977.560 1399.600 977.960 1400.000 ;
    END
  END class_scores_la[53]
  PIN class_scores_la[54]
    DIRECTION OUTPUT ;
    USE SIGNAL ;
    ANTENNADIFFAREA 0.708600 ;
    PORT
      LAYER Metal2 ;
        RECT 1028.440 1399.600 1028.840 1400.000 ;
    END
  END class_scores_la[54]
  PIN class_scores_la[55]
    DIRECTION OUTPUT ;
    USE SIGNAL ;
    ANTENNADIFFAREA 0.708600 ;
    PORT
      LAYER Metal2 ;
        RECT 1043.800 1399.600 1044.200 1400.000 ;
    END
  END class_scores_la[55]
  PIN class_scores_la[56]
    DIRECTION OUTPUT ;
    USE SIGNAL ;
    ANTENNADIFFAREA 0.708600 ;
    PORT
      LAYER Metal2 ;
        RECT 1020.760 1399.600 1021.160 1400.000 ;
    END
  END class_scores_la[56]
  PIN class_scores_la[57]
    DIRECTION OUTPUT ;
    USE SIGNAL ;
    ANTENNADIFFAREA 0.708600 ;
    PORT
      LAYER Metal2 ;
        RECT 1010.200 1399.600 1010.600 1400.000 ;
    END
  END class_scores_la[57]
  PIN class_scores_la[58]
    DIRECTION OUTPUT ;
    USE SIGNAL ;
    ANTENNADIFFAREA 0.708600 ;
    PORT
      LAYER Metal2 ;
        RECT 978.520 1399.600 978.920 1400.000 ;
    END
  END class_scores_la[58]
  PIN class_scores_la[59]
    DIRECTION OUTPUT ;
    USE SIGNAL ;
    ANTENNADIFFAREA 0.708600 ;
    PORT
      LAYER Metal2 ;
        RECT 963.160 1399.600 963.560 1400.000 ;
    END
  END class_scores_la[59]
  PIN class_scores_la[5]
    DIRECTION OUTPUT ;
    USE SIGNAL ;
    ANTENNADIFFAREA 0.708600 ;
    PORT
      LAYER Metal3 ;
        RECT 1399.600 1144.300 1400.000 1144.700 ;
    END
  END class_scores_la[5]
  PIN class_scores_la[60]
    DIRECTION OUTPUT ;
    USE SIGNAL ;
    ANTENNADIFFAREA 0.708600 ;
    PORT
      LAYER Metal2 ;
        RECT 1037.080 1399.600 1037.480 1400.000 ;
    END
  END class_scores_la[60]
  PIN class_scores_la[61]
    DIRECTION OUTPUT ;
    USE SIGNAL ;
    ANTENNADIFFAREA 0.708600 ;
    PORT
      LAYER Metal2 ;
        RECT 1051.480 1399.600 1051.880 1400.000 ;
    END
  END class_scores_la[61]
  PIN class_scores_la[62]
    DIRECTION OUTPUT ;
    USE SIGNAL ;
    ANTENNADIFFAREA 0.708600 ;
    PORT
      LAYER Metal2 ;
        RECT 1050.520 1399.600 1050.920 1400.000 ;
    END
  END class_scores_la[62]
  PIN class_scores_la[63]
    DIRECTION OUTPUT ;
    USE SIGNAL ;
    ANTENNADIFFAREA 0.708600 ;
    PORT
      LAYER Metal2 ;
        RECT 1071.640 1399.600 1072.040 1400.000 ;
    END
  END class_scores_la[63]
  PIN class_scores_la[64]
    DIRECTION OUTPUT ;
    USE SIGNAL ;
    ANTENNADIFFAREA 0.708600 ;
    PORT
      LAYER Metal3 ;
        RECT 1399.600 1228.300 1400.000 1228.700 ;
    END
  END class_scores_la[64]
  PIN class_scores_la[65]
    DIRECTION OUTPUT ;
    USE SIGNAL ;
    ANTENNADIFFAREA 0.708600 ;
    PORT
      LAYER Metal3 ;
        RECT 1399.600 1230.820 1400.000 1231.220 ;
    END
  END class_scores_la[65]
  PIN class_scores_la[66]
    DIRECTION OUTPUT ;
    USE SIGNAL ;
    ANTENNADIFFAREA 0.708600 ;
    PORT
      LAYER Metal3 ;
        RECT 1399.600 1201.420 1400.000 1201.820 ;
    END
  END class_scores_la[66]
  PIN class_scores_la[67]
    DIRECTION OUTPUT ;
    USE SIGNAL ;
    ANTENNADIFFAREA 0.708600 ;
    PORT
      LAYER Metal3 ;
        RECT 1399.600 1187.980 1400.000 1188.380 ;
    END
  END class_scores_la[67]
  PIN class_scores_la[68]
    DIRECTION OUTPUT ;
    USE SIGNAL ;
    ANTENNADIFFAREA 0.708600 ;
    PORT
      LAYER Metal3 ;
        RECT 1399.600 1178.740 1400.000 1179.140 ;
    END
  END class_scores_la[68]
  PIN class_scores_la[69]
    DIRECTION OUTPUT ;
    USE SIGNAL ;
    ANTENNADIFFAREA 0.708600 ;
    PORT
      LAYER Metal3 ;
        RECT 1399.600 1154.380 1400.000 1154.780 ;
    END
  END class_scores_la[69]
  PIN class_scores_la[6]
    DIRECTION OUTPUT ;
    USE SIGNAL ;
    ANTENNADIFFAREA 0.708600 ;
    PORT
      LAYER Metal3 ;
        RECT 1399.600 1109.860 1400.000 1110.260 ;
    END
  END class_scores_la[6]
  PIN class_scores_la[70]
    DIRECTION OUTPUT ;
    USE SIGNAL ;
    ANTENNADIFFAREA 0.708600 ;
    PORT
      LAYER Metal3 ;
        RECT 1399.600 1115.740 1400.000 1116.140 ;
    END
  END class_scores_la[70]
  PIN class_scores_la[71]
    DIRECTION OUTPUT ;
    USE SIGNAL ;
    ANTENNADIFFAREA 0.708600 ;
    PORT
      LAYER Metal3 ;
        RECT 1399.600 1128.340 1400.000 1128.740 ;
    END
  END class_scores_la[71]
  PIN class_scores_la[72]
    DIRECTION OUTPUT ;
    USE SIGNAL ;
    ANTENNADIFFAREA 0.708600 ;
    PORT
      LAYER Metal3 ;
        RECT 1399.600 1127.500 1400.000 1127.900 ;
    END
  END class_scores_la[72]
  PIN class_scores_la[73]
    DIRECTION OUTPUT ;
    USE SIGNAL ;
    ANTENNADIFFAREA 0.708600 ;
    PORT
      LAYER Metal3 ;
        RECT 1399.600 1124.980 1400.000 1125.380 ;
    END
  END class_scores_la[73]
  PIN class_scores_la[74]
    DIRECTION OUTPUT ;
    USE SIGNAL ;
    ANTENNADIFFAREA 0.708600 ;
    PORT
      LAYER Metal2 ;
        RECT 1150.360 1399.600 1150.760 1400.000 ;
    END
  END class_scores_la[74]
  PIN class_scores_la[75]
    DIRECTION OUTPUT ;
    USE SIGNAL ;
    ANTENNADIFFAREA 0.708600 ;
    PORT
      LAYER Metal2 ;
        RECT 1140.760 1399.600 1141.160 1400.000 ;
    END
  END class_scores_la[75]
  PIN class_scores_la[76]
    DIRECTION OUTPUT ;
    USE SIGNAL ;
    ANTENNADIFFAREA 0.708600 ;
    PORT
      LAYER Metal2 ;
        RECT 1128.280 1399.600 1128.680 1400.000 ;
    END
  END class_scores_la[76]
  PIN class_scores_la[77]
    DIRECTION OUTPUT ;
    USE SIGNAL ;
    ANTENNADIFFAREA 0.708600 ;
    PORT
      LAYER Metal2 ;
        RECT 1101.400 1399.600 1101.800 1400.000 ;
    END
  END class_scores_la[77]
  PIN class_scores_la[78]
    DIRECTION OUTPUT ;
    USE SIGNAL ;
    ANTENNADIFFAREA 0.708600 ;
    PORT
      LAYER Metal2 ;
        RECT 1087.960 1399.600 1088.360 1400.000 ;
    END
  END class_scores_la[78]
  PIN class_scores_la[79]
    DIRECTION OUTPUT ;
    USE SIGNAL ;
    ANTENNADIFFAREA 0.708600 ;
    PORT
      LAYER Metal2 ;
        RECT 1080.280 1399.600 1080.680 1400.000 ;
    END
  END class_scores_la[79]
  PIN class_scores_la[7]
    DIRECTION OUTPUT ;
    USE SIGNAL ;
    ANTENNADIFFAREA 0.708600 ;
    PORT
      LAYER Metal3 ;
        RECT 1399.600 1130.020 1400.000 1130.420 ;
    END
  END class_scores_la[7]
  PIN class_scores_la[80]
    DIRECTION OUTPUT ;
    USE SIGNAL ;
    ANTENNADIFFAREA 0.708600 ;
    PORT
      LAYER Metal2 ;
        RECT 1058.200 1399.600 1058.600 1400.000 ;
    END
  END class_scores_la[80]
  PIN class_scores_la[81]
    DIRECTION OUTPUT ;
    USE SIGNAL ;
    ANTENNADIFFAREA 0.708600 ;
    PORT
      LAYER Metal2 ;
        RECT 1040.920 1399.600 1041.320 1400.000 ;
    END
  END class_scores_la[81]
  PIN class_scores_la[82]
    DIRECTION OUTPUT ;
    USE SIGNAL ;
    ANTENNADIFFAREA 0.708600 ;
    PORT
      LAYER Metal2 ;
        RECT 1007.320 1399.600 1007.720 1400.000 ;
    END
  END class_scores_la[82]
  PIN class_scores_la[83]
    DIRECTION OUTPUT ;
    USE SIGNAL ;
    ANTENNADIFFAREA 0.708600 ;
    PORT
      LAYER Metal2 ;
        RECT 991.000 1399.600 991.400 1400.000 ;
    END
  END class_scores_la[83]
  PIN class_scores_la[84]
    DIRECTION OUTPUT ;
    USE SIGNAL ;
    ANTENNADIFFAREA 0.708600 ;
    PORT
      LAYER Metal2 ;
        RECT 986.200 1399.600 986.600 1400.000 ;
    END
  END class_scores_la[84]
  PIN class_scores_la[85]
    DIRECTION OUTPUT ;
    USE SIGNAL ;
    ANTENNADIFFAREA 0.708600 ;
    PORT
      LAYER Metal2 ;
        RECT 1004.440 1399.600 1004.840 1400.000 ;
    END
  END class_scores_la[85]
  PIN class_scores_la[86]
    DIRECTION OUTPUT ;
    USE SIGNAL ;
    ANTENNADIFFAREA 0.708600 ;
    PORT
      LAYER Metal2 ;
        RECT 1019.800 1399.600 1020.200 1400.000 ;
    END
  END class_scores_la[86]
  PIN class_scores_la[87]
    DIRECTION OUTPUT ;
    USE SIGNAL ;
    ANTENNADIFFAREA 0.708600 ;
    PORT
      LAYER Metal2 ;
        RECT 1049.560 1399.600 1049.960 1400.000 ;
    END
  END class_scores_la[87]
  PIN class_scores_la[88]
    DIRECTION OUTPUT ;
    USE SIGNAL ;
    ANTENNADIFFAREA 0.708600 ;
    PORT
      LAYER Metal2 ;
        RECT 1013.080 1399.600 1013.480 1400.000 ;
    END
  END class_scores_la[88]
  PIN class_scores_la[89]
    DIRECTION OUTPUT ;
    USE SIGNAL ;
    ANTENNADIFFAREA 0.708600 ;
    PORT
      LAYER Metal2 ;
        RECT 1001.560 1399.600 1001.960 1400.000 ;
    END
  END class_scores_la[89]
  PIN class_scores_la[8]
    DIRECTION OUTPUT ;
    USE SIGNAL ;
    ANTENNADIFFAREA 0.708600 ;
    PORT
      LAYER Metal3 ;
        RECT 1399.600 1107.340 1400.000 1107.740 ;
    END
  END class_scores_la[8]
  PIN class_scores_la[90]
    DIRECTION OUTPUT ;
    USE SIGNAL ;
    ANTENNADIFFAREA 0.708600 ;
    PORT
      LAYER Metal2 ;
        RECT 985.240 1399.600 985.640 1400.000 ;
    END
  END class_scores_la[90]
  PIN class_scores_la[91]
    DIRECTION OUTPUT ;
    USE SIGNAL ;
    ANTENNADIFFAREA 0.708600 ;
    PORT
      LAYER Metal2 ;
        RECT 979.480 1399.600 979.880 1400.000 ;
    END
  END class_scores_la[91]
  PIN class_scores_la[92]
    DIRECTION OUTPUT ;
    USE SIGNAL ;
    ANTENNADIFFAREA 0.708600 ;
    PORT
      LAYER Metal2 ;
        RECT 1035.160 1399.600 1035.560 1400.000 ;
    END
  END class_scores_la[92]
  PIN class_scores_la[93]
    DIRECTION OUTPUT ;
    USE SIGNAL ;
    ANTENNADIFFAREA 0.708600 ;
    PORT
      LAYER Metal2 ;
        RECT 1064.920 1399.600 1065.320 1400.000 ;
    END
  END class_scores_la[93]
  PIN class_scores_la[94]
    DIRECTION OUTPUT ;
    USE SIGNAL ;
    ANTENNADIFFAREA 0.708600 ;
    PORT
      LAYER Metal2 ;
        RECT 1063.960 1399.600 1064.360 1400.000 ;
    END
  END class_scores_la[94]
  PIN class_scores_la[95]
    DIRECTION OUTPUT ;
    USE SIGNAL ;
    ANTENNADIFFAREA 0.708600 ;
    PORT
      LAYER Metal2 ;
        RECT 1070.680 1399.600 1071.080 1400.000 ;
    END
  END class_scores_la[95]
  PIN class_scores_la[96]
    DIRECTION OUTPUT ;
    USE SIGNAL ;
    ANTENNADIFFAREA 0.708600 ;
    PORT
      LAYER Metal3 ;
        RECT 1399.600 1203.940 1400.000 1204.340 ;
    END
  END class_scores_la[96]
  PIN class_scores_la[97]
    DIRECTION OUTPUT ;
    USE SIGNAL ;
    ANTENNADIFFAREA 0.708600 ;
    PORT
      LAYER Metal3 ;
        RECT 1399.600 1222.420 1400.000 1222.820 ;
    END
  END class_scores_la[97]
  PIN class_scores_la[98]
    DIRECTION OUTPUT ;
    USE SIGNAL ;
    ANTENNADIFFAREA 0.708600 ;
    PORT
      LAYER Metal3 ;
        RECT 1399.600 1224.940 1400.000 1225.340 ;
    END
  END class_scores_la[98]
  PIN class_scores_la[99]
    DIRECTION OUTPUT ;
    USE SIGNAL ;
    ANTENNADIFFAREA 0.708600 ;
    PORT
      LAYER Metal3 ;
        RECT 1399.600 1191.340 1400.000 1191.740 ;
    END
  END class_scores_la[99]
  PIN class_scores_la[9]
    DIRECTION OUTPUT ;
    USE SIGNAL ;
    ANTENNADIFFAREA 0.708600 ;
    PORT
      LAYER Metal3 ;
        RECT 1399.600 1108.180 1400.000 1108.580 ;
    END
  END class_scores_la[9]
  PIN clk
    DIRECTION INPUT ;
    USE SIGNAL ;
    ANTENNAGATEAREA 1.450800 ;
    PORT
      LAYER Metal3 ;
        RECT 1399.600 29.620 1400.000 30.020 ;
    END
  END clk
  PIN done
    DIRECTION OUTPUT ;
    USE SIGNAL ;
    ANTENNADIFFAREA 0.708600 ;
    PORT
      LAYER Metal2 ;
        RECT 952.600 1399.600 953.000 1400.000 ;
    END
  END done
  PIN error
    DIRECTION OUTPUT ;
    USE SIGNAL ;
    ANTENNADIFFAREA 0.708600 ;
    PORT
      LAYER Metal2 ;
        RECT 943.000 1399.600 943.400 1400.000 ;
    END
  END error
  PIN error_code[0]
    DIRECTION OUTPUT ;
    USE SIGNAL ;
    ANTENNADIFFAREA 0.708600 ;
    PORT
      LAYER Metal2 ;
        RECT 951.640 1399.600 952.040 1400.000 ;
    END
  END error_code[0]
  PIN error_code[1]
    DIRECTION OUTPUT ;
    USE SIGNAL ;
    ANTENNADIFFAREA 0.708600 ;
    PORT
      LAYER Metal2 ;
        RECT 941.080 1399.600 941.480 1400.000 ;
    END
  END error_code[1]
  PIN error_code[2]
    DIRECTION OUTPUT ;
    USE SIGNAL ;
    ANTENNADIFFAREA 0.708600 ;
    PORT
      LAYER Metal2 ;
        RECT 944.920 1399.600 945.320 1400.000 ;
    END
  END error_code[2]
  PIN error_code[3]
    DIRECTION OUTPUT ;
    USE SIGNAL ;
    ANTENNADIFFAREA 0.708600 ;
    PORT
      LAYER Metal2 ;
        RECT 945.880 1399.600 946.280 1400.000 ;
    END
  END error_code[3]
  PIN gamma_reg[0]
    DIRECTION OUTPUT ;
    USE SIGNAL ;
    ANTENNADIFFAREA 0.708600 ;
    PORT
      LAYER Metal2 ;
        RECT 1137.880 1399.600 1138.280 1400.000 ;
    END
  END gamma_reg[0]
  PIN gamma_reg[10]
    DIRECTION OUTPUT ;
    USE SIGNAL ;
    ANTENNADIFFAREA 0.708600 ;
    PORT
      LAYER Metal2 ;
        RECT 1120.600 1399.600 1121.000 1400.000 ;
    END
  END gamma_reg[10]
  PIN gamma_reg[11]
    DIRECTION OUTPUT ;
    USE SIGNAL ;
    ANTENNADIFFAREA 0.708600 ;
    PORT
      LAYER Metal2 ;
        RECT 1112.920 1399.600 1113.320 1400.000 ;
    END
  END gamma_reg[11]
  PIN gamma_reg[12]
    DIRECTION OUTPUT ;
    USE SIGNAL ;
    ANTENNADIFFAREA 0.708600 ;
    PORT
      LAYER Metal2 ;
        RECT 1096.600 1399.600 1097.000 1400.000 ;
    END
  END gamma_reg[12]
  PIN gamma_reg[13]
    DIRECTION OUTPUT ;
    USE SIGNAL ;
    ANTENNADIFFAREA 0.708600 ;
    PORT
      LAYER Metal2 ;
        RECT 956.440 1399.600 956.840 1400.000 ;
    END
  END gamma_reg[13]
  PIN gamma_reg[14]
    DIRECTION OUTPUT ;
    USE SIGNAL ;
    ANTENNADIFFAREA 0.708600 ;
    PORT
      LAYER Metal2 ;
        RECT 960.280 1399.600 960.680 1400.000 ;
    END
  END gamma_reg[14]
  PIN gamma_reg[15]
    DIRECTION OUTPUT ;
    USE SIGNAL ;
    ANTENNADIFFAREA 0.708600 ;
    PORT
      LAYER Metal2 ;
        RECT 1002.520 1399.600 1002.920 1400.000 ;
    END
  END gamma_reg[15]
  PIN gamma_reg[1]
    DIRECTION OUTPUT ;
    USE SIGNAL ;
    ANTENNADIFFAREA 0.708600 ;
    PORT
      LAYER Metal2 ;
        RECT 1131.160 1399.600 1131.560 1400.000 ;
    END
  END gamma_reg[1]
  PIN gamma_reg[2]
    DIRECTION OUTPUT ;
    USE SIGNAL ;
    ANTENNADIFFAREA 0.708600 ;
    PORT
      LAYER Metal2 ;
        RECT 1146.520 1399.600 1146.920 1400.000 ;
    END
  END gamma_reg[2]
  PIN gamma_reg[3]
    DIRECTION OUTPUT ;
    USE SIGNAL ;
    ANTENNADIFFAREA 0.708600 ;
    PORT
      LAYER Metal2 ;
        RECT 1135.000 1399.600 1135.400 1400.000 ;
    END
  END gamma_reg[3]
  PIN gamma_reg[4]
    DIRECTION OUTPUT ;
    USE SIGNAL ;
    ANTENNADIFFAREA 0.708600 ;
    PORT
      LAYER Metal2 ;
        RECT 1160.920 1399.600 1161.320 1400.000 ;
    END
  END gamma_reg[4]
  PIN gamma_reg[5]
    DIRECTION OUTPUT ;
    USE SIGNAL ;
    ANTENNADIFFAREA 0.708600 ;
    PORT
      LAYER Metal2 ;
        RECT 1157.080 1399.600 1157.480 1400.000 ;
    END
  END gamma_reg[5]
  PIN gamma_reg[6]
    DIRECTION OUTPUT ;
    USE SIGNAL ;
    ANTENNADIFFAREA 0.708600 ;
    PORT
      LAYER Metal2 ;
        RECT 1158.040 1399.600 1158.440 1400.000 ;
    END
  END gamma_reg[6]
  PIN gamma_reg[7]
    DIRECTION OUTPUT ;
    USE SIGNAL ;
    ANTENNADIFFAREA 0.708600 ;
    PORT
      LAYER Metal2 ;
        RECT 1153.240 1399.600 1153.640 1400.000 ;
    END
  END gamma_reg[7]
  PIN gamma_reg[8]
    DIRECTION OUTPUT ;
    USE SIGNAL ;
    ANTENNADIFFAREA 0.708600 ;
    PORT
      LAYER Metal2 ;
        RECT 1103.320 1399.600 1103.720 1400.000 ;
    END
  END gamma_reg[8]
  PIN gamma_reg[9]
    DIRECTION OUTPUT ;
    USE SIGNAL ;
    ANTENNADIFFAREA 0.708600 ;
    PORT
      LAYER Metal2 ;
        RECT 1105.240 1399.600 1105.640 1400.000 ;
    END
  END gamma_reg[9]
  PIN kernel_out[0]
    DIRECTION OUTPUT ;
    USE SIGNAL ;
    ANTENNADIFFAREA 0.708600 ;
    PORT
      LAYER Metal3 ;
        RECT 1399.600 978.820 1400.000 979.220 ;
    END
  END kernel_out[0]
  PIN kernel_out[10]
    DIRECTION OUTPUT ;
    USE SIGNAL ;
    ANTENNADIFFAREA 0.708600 ;
    PORT
      LAYER Metal3 ;
        RECT 1399.600 1010.740 1400.000 1011.140 ;
    END
  END kernel_out[10]
  PIN kernel_out[11]
    DIRECTION OUTPUT ;
    USE SIGNAL ;
    ANTENNADIFFAREA 0.708600 ;
    PORT
      LAYER Metal3 ;
        RECT 1399.600 984.700 1400.000 985.100 ;
    END
  END kernel_out[11]
  PIN kernel_out[12]
    DIRECTION OUTPUT ;
    USE SIGNAL ;
    ANTENNADIFFAREA 0.708600 ;
    PORT
      LAYER Metal3 ;
        RECT 1399.600 1012.420 1400.000 1012.820 ;
    END
  END kernel_out[12]
  PIN kernel_out[13]
    DIRECTION OUTPUT ;
    USE SIGNAL ;
    ANTENNADIFFAREA 0.708600 ;
    PORT
      LAYER Metal3 ;
        RECT 1399.600 1009.900 1400.000 1010.300 ;
    END
  END kernel_out[13]
  PIN kernel_out[14]
    DIRECTION OUTPUT ;
    USE SIGNAL ;
    ANTENNADIFFAREA 0.708600 ;
    PORT
      LAYER Metal3 ;
        RECT 1399.600 1014.100 1400.000 1014.500 ;
    END
  END kernel_out[14]
  PIN kernel_out[15]
    DIRECTION OUTPUT ;
    USE SIGNAL ;
    ANTENNADIFFAREA 0.708600 ;
    PORT
      LAYER Metal3 ;
        RECT 1399.600 1015.780 1400.000 1016.180 ;
    END
  END kernel_out[15]
  PIN kernel_out[1]
    DIRECTION OUTPUT ;
    USE SIGNAL ;
    ANTENNADIFFAREA 0.708600 ;
    PORT
      LAYER Metal3 ;
        RECT 1399.600 965.380 1400.000 965.780 ;
    END
  END kernel_out[1]
  PIN kernel_out[2]
    DIRECTION OUTPUT ;
    USE SIGNAL ;
    ANTENNADIFFAREA 0.708600 ;
    PORT
      LAYER Metal3 ;
        RECT 1399.600 972.100 1400.000 972.500 ;
    END
  END kernel_out[2]
  PIN kernel_out[3]
    DIRECTION OUTPUT ;
    USE SIGNAL ;
    ANTENNADIFFAREA 0.708600 ;
    PORT
      LAYER Metal3 ;
        RECT 1399.600 973.780 1400.000 974.180 ;
    END
  END kernel_out[3]
  PIN kernel_out[4]
    DIRECTION OUTPUT ;
    USE SIGNAL ;
    ANTENNADIFFAREA 0.708600 ;
    PORT
      LAYER Metal3 ;
        RECT 1399.600 967.900 1400.000 968.300 ;
    END
  END kernel_out[4]
  PIN kernel_out[5]
    DIRECTION OUTPUT ;
    USE SIGNAL ;
    ANTENNADIFFAREA 0.708600 ;
    PORT
      LAYER Metal3 ;
        RECT 1399.600 975.460 1400.000 975.860 ;
    END
  END kernel_out[5]
  PIN kernel_out[6]
    DIRECTION OUTPUT ;
    USE SIGNAL ;
    ANTENNADIFFAREA 0.708600 ;
    PORT
      LAYER Metal3 ;
        RECT 1399.600 977.140 1400.000 977.540 ;
    END
  END kernel_out[6]
  PIN kernel_out[7]
    DIRECTION OUTPUT ;
    USE SIGNAL ;
    ANTENNADIFFAREA 0.708600 ;
    PORT
      LAYER Metal3 ;
        RECT 1399.600 986.380 1400.000 986.780 ;
    END
  END kernel_out[7]
  PIN kernel_out[8]
    DIRECTION OUTPUT ;
    USE SIGNAL ;
    ANTENNADIFFAREA 0.708600 ;
    PORT
      LAYER Metal3 ;
        RECT 1399.600 1024.180 1400.000 1024.580 ;
    END
  END kernel_out[8]
  PIN kernel_out[9]
    DIRECTION OUTPUT ;
    USE SIGNAL ;
    ANTENNADIFFAREA 0.708600 ;
    PORT
      LAYER Metal3 ;
        RECT 1399.600 1013.260 1400.000 1013.660 ;
    END
  END kernel_out[9]
  PIN kernel_ready
    DIRECTION INPUT ;
    USE SIGNAL ;
    ANTENNAGATEAREA 0.109200 ;
    PORT
      LAYER Metal2 ;
        RECT 961.240 1399.600 961.640 1400.000 ;
    END
  END kernel_ready
  PIN kernel_valid
    DIRECTION OUTPUT ;
    USE SIGNAL ;
    ANTENNADIFFAREA 0.708600 ;
    PORT
      LAYER Metal2 ;
        RECT 962.200 1399.600 962.600 1400.000 ;
    END
  END kernel_valid
  PIN num_samples[0]
    DIRECTION INPUT ;
    USE SIGNAL ;
    ANTENNAGATEAREA 0.109200 ;
    PORT
      LAYER Metal2 ;
        RECT 931.480 1399.600 931.880 1400.000 ;
    END
  END num_samples[0]
  PIN num_samples[1]
    DIRECTION INPUT ;
    USE SIGNAL ;
    ANTENNAGATEAREA 0.109200 ;
    PORT
      LAYER Metal2 ;
        RECT 930.520 1399.600 930.920 1400.000 ;
    END
  END num_samples[1]
  PIN num_samples[2]
    DIRECTION INPUT ;
    USE SIGNAL ;
    ANTENNAGATEAREA 0.109200 ;
    PORT
      LAYER Metal2 ;
        RECT 927.640 1399.600 928.040 1400.000 ;
    END
  END num_samples[2]
  PIN num_samples[3]
    DIRECTION INPUT ;
    USE SIGNAL ;
    ANTENNAGATEAREA 0.109200 ;
    PORT
      LAYER Metal2 ;
        RECT 925.720 1399.600 926.120 1400.000 ;
    END
  END num_samples[3]
  PIN num_samples[4]
    DIRECTION INPUT ;
    USE SIGNAL ;
    ANTENNAGATEAREA 0.109200 ;
    PORT
      LAYER Metal2 ;
        RECT 928.600 1399.600 929.000 1400.000 ;
    END
  END num_samples[4]
  PIN num_samples[5]
    DIRECTION INPUT ;
    USE SIGNAL ;
    ANTENNAGATEAREA 0.109200 ;
    PORT
      LAYER Metal2 ;
        RECT 924.760 1399.600 925.160 1400.000 ;
    END
  END num_samples[5]
  PIN num_samples[6]
    DIRECTION INPUT ;
    USE SIGNAL ;
    ANTENNAGATEAREA 0.109200 ;
    PORT
      LAYER Metal2 ;
        RECT 920.920 1399.600 921.320 1400.000 ;
    END
  END num_samples[6]
  PIN num_samples[7]
    DIRECTION INPUT ;
    USE SIGNAL ;
    ANTENNAGATEAREA 0.109200 ;
    PORT
      LAYER Metal2 ;
        RECT 919.960 1399.600 920.360 1400.000 ;
    END
  END num_samples[7]
  PIN num_samples[8]
    DIRECTION INPUT ;
    USE SIGNAL ;
    ANTENNAGATEAREA 0.109200 ;
    PORT
      LAYER Metal2 ;
        RECT 923.800 1399.600 924.200 1400.000 ;
    END
  END num_samples[8]
  PIN num_samples[9]
    DIRECTION INPUT ;
    USE SIGNAL ;
    ANTENNAGATEAREA 0.109200 ;
    PORT
      LAYER Metal2 ;
        RECT 921.880 1399.600 922.280 1400.000 ;
    END
  END num_samples[9]
  PIN num_sv_per_class_flat[0]
    DIRECTION INPUT ;
    USE SIGNAL ;
    ANTENNAGATEAREA 0.109200 ;
    PORT
      LAYER Metal3 ;
        RECT 1399.600 1095.580 1400.000 1095.980 ;
    END
  END num_sv_per_class_flat[0]
  PIN num_sv_per_class_flat[10]
    DIRECTION INPUT ;
    USE SIGNAL ;
    ANTENNAGATEAREA 0.109200 ;
    PORT
      LAYER Metal3 ;
        RECT 1399.600 1066.180 1400.000 1066.580 ;
    END
  END num_sv_per_class_flat[10]
  PIN num_sv_per_class_flat[11]
    DIRECTION INPUT ;
    USE SIGNAL ;
    ANTENNAGATEAREA 0.109200 ;
    PORT
      LAYER Metal3 ;
        RECT 1399.600 1020.820 1400.000 1021.220 ;
    END
  END num_sv_per_class_flat[11]
  PIN num_sv_per_class_flat[12]
    DIRECTION INPUT ;
    USE SIGNAL ;
    ANTENNAGATEAREA 0.109200 ;
    PORT
      LAYER Metal3 ;
        RECT 1399.600 990.580 1400.000 990.980 ;
    END
  END num_sv_per_class_flat[12]
  PIN num_sv_per_class_flat[13]
    DIRECTION INPUT ;
    USE SIGNAL ;
    ANTENNAGATEAREA 0.109200 ;
    PORT
      LAYER Metal3 ;
        RECT 1399.600 981.340 1400.000 981.740 ;
    END
  END num_sv_per_class_flat[13]
  PIN num_sv_per_class_flat[14]
    DIRECTION INPUT ;
    USE SIGNAL ;
    ANTENNAGATEAREA 0.109200 ;
    PORT
      LAYER Metal2 ;
        RECT 946.840 1399.600 947.240 1400.000 ;
    END
  END num_sv_per_class_flat[14]
  PIN num_sv_per_class_flat[15]
    DIRECTION INPUT ;
    USE SIGNAL ;
    ANTENNAGATEAREA 0.109200 ;
    PORT
      LAYER Metal2 ;
        RECT 935.320 1399.600 935.720 1400.000 ;
    END
  END num_sv_per_class_flat[15]
  PIN num_sv_per_class_flat[16]
    DIRECTION INPUT ;
    USE SIGNAL ;
    ANTENNAGATEAREA 0.109200 ;
    PORT
      LAYER Metal3 ;
        RECT 1399.600 1098.100 1400.000 1098.500 ;
    END
  END num_sv_per_class_flat[16]
  PIN num_sv_per_class_flat[17]
    DIRECTION INPUT ;
    USE SIGNAL ;
    ANTENNAGATEAREA 0.109200 ;
    PORT
      LAYER Metal3 ;
        RECT 1399.600 1099.780 1400.000 1100.180 ;
    END
  END num_sv_per_class_flat[17]
  PIN num_sv_per_class_flat[18]
    DIRECTION INPUT ;
    USE SIGNAL ;
    ANTENNAGATEAREA 0.109200 ;
    PORT
      LAYER Metal3 ;
        RECT 1399.600 1058.620 1400.000 1059.020 ;
    END
  END num_sv_per_class_flat[18]
  PIN num_sv_per_class_flat[19]
    DIRECTION INPUT ;
    USE SIGNAL ;
    ANTENNAGATEAREA 0.109200 ;
    PORT
      LAYER Metal3 ;
        RECT 1399.600 1030.060 1400.000 1030.460 ;
    END
  END num_sv_per_class_flat[19]
  PIN num_sv_per_class_flat[1]
    DIRECTION INPUT ;
    USE SIGNAL ;
    ANTENNAGATEAREA 0.109200 ;
    PORT
      LAYER Metal2 ;
        RECT 999.640 1399.600 1000.040 1400.000 ;
    END
  END num_sv_per_class_flat[1]
  PIN num_sv_per_class_flat[20]
    DIRECTION INPUT ;
    USE SIGNAL ;
    ANTENNAGATEAREA 0.109200 ;
    PORT
      LAYER Metal3 ;
        RECT 1399.600 974.620 1400.000 975.020 ;
    END
  END num_sv_per_class_flat[20]
  PIN num_sv_per_class_flat[21]
    DIRECTION INPUT ;
    USE SIGNAL ;
    ANTENNAGATEAREA 0.109200 ;
    PORT
      LAYER Metal3 ;
        RECT 1399.600 972.940 1400.000 973.340 ;
    END
  END num_sv_per_class_flat[21]
  PIN num_sv_per_class_flat[22]
    DIRECTION INPUT ;
    USE SIGNAL ;
    ANTENNAGATEAREA 0.109200 ;
    PORT
      LAYER Metal2 ;
        RECT 954.520 1399.600 954.920 1400.000 ;
    END
  END num_sv_per_class_flat[22]
  PIN num_sv_per_class_flat[23]
    DIRECTION INPUT ;
    USE SIGNAL ;
    ANTENNAGATEAREA 0.109200 ;
    PORT
      LAYER Metal2 ;
        RECT 943.960 1399.600 944.360 1400.000 ;
    END
  END num_sv_per_class_flat[23]
  PIN num_sv_per_class_flat[24]
    DIRECTION INPUT ;
    USE SIGNAL ;
    ANTENNAGATEAREA 0.109200 ;
    PORT
      LAYER Metal3 ;
        RECT 1399.600 1078.780 1400.000 1079.180 ;
    END
  END num_sv_per_class_flat[24]
  PIN num_sv_per_class_flat[25]
    DIRECTION INPUT ;
    USE SIGNAL ;
    ANTENNAGATEAREA 0.109200 ;
    PORT
      LAYER Metal3 ;
        RECT 1399.600 1077.100 1400.000 1077.500 ;
    END
  END num_sv_per_class_flat[25]
  PIN num_sv_per_class_flat[26]
    DIRECTION INPUT ;
    USE SIGNAL ;
    ANTENNAGATEAREA 0.109200 ;
    PORT
      LAYER Metal3 ;
        RECT 1399.600 1057.780 1400.000 1058.180 ;
    END
  END num_sv_per_class_flat[26]
  PIN num_sv_per_class_flat[27]
    DIRECTION INPUT ;
    USE SIGNAL ;
    ANTENNAGATEAREA 0.109200 ;
    PORT
      LAYER Metal3 ;
        RECT 1399.600 1037.620 1400.000 1038.020 ;
    END
  END num_sv_per_class_flat[27]
  PIN num_sv_per_class_flat[28]
    DIRECTION INPUT ;
    USE SIGNAL ;
    ANTENNAGATEAREA 0.109200 ;
    PORT
      LAYER Metal3 ;
        RECT 1399.600 970.420 1400.000 970.820 ;
    END
  END num_sv_per_class_flat[28]
  PIN num_sv_per_class_flat[29]
    DIRECTION INPUT ;
    USE SIGNAL ;
    ANTENNAGATEAREA 0.109200 ;
    PORT
      LAYER Metal3 ;
        RECT 1399.600 971.260 1400.000 971.660 ;
    END
  END num_sv_per_class_flat[29]
  PIN num_sv_per_class_flat[2]
    DIRECTION INPUT ;
    USE SIGNAL ;
    ANTENNAGATEAREA 0.109200 ;
    PORT
      LAYER Metal3 ;
        RECT 1399.600 1060.300 1400.000 1060.700 ;
    END
  END num_sv_per_class_flat[2]
  PIN num_sv_per_class_flat[30]
    DIRECTION INPUT ;
    USE SIGNAL ;
    ANTENNAGATEAREA 0.109200 ;
    PORT
      LAYER Metal3 ;
        RECT 1399.600 976.300 1400.000 976.700 ;
    END
  END num_sv_per_class_flat[30]
  PIN num_sv_per_class_flat[31]
    DIRECTION INPUT ;
    USE SIGNAL ;
    ANTENNAGATEAREA 0.109200 ;
    PORT
      LAYER Metal2 ;
        RECT 950.680 1399.600 951.080 1400.000 ;
    END
  END num_sv_per_class_flat[31]
  PIN num_sv_per_class_flat[32]
    DIRECTION INPUT ;
    USE SIGNAL ;
    ANTENNAGATEAREA 0.109200 ;
    PORT
      LAYER Metal3 ;
        RECT 1399.600 1085.500 1400.000 1085.900 ;
    END
  END num_sv_per_class_flat[32]
  PIN num_sv_per_class_flat[33]
    DIRECTION INPUT ;
    USE SIGNAL ;
    ANTENNAGATEAREA 0.109200 ;
    PORT
      LAYER Metal3 ;
        RECT 1399.600 1082.140 1400.000 1082.540 ;
    END
  END num_sv_per_class_flat[33]
  PIN num_sv_per_class_flat[34]
    DIRECTION INPUT ;
    USE SIGNAL ;
    ANTENNAGATEAREA 0.109200 ;
    PORT
      LAYER Metal3 ;
        RECT 1399.600 1056.100 1400.000 1056.500 ;
    END
  END num_sv_per_class_flat[34]
  PIN num_sv_per_class_flat[35]
    DIRECTION INPUT ;
    USE SIGNAL ;
    ANTENNAGATEAREA 0.109200 ;
    PORT
      LAYER Metal3 ;
        RECT 1399.600 1040.140 1400.000 1040.540 ;
    END
  END num_sv_per_class_flat[35]
  PIN num_sv_per_class_flat[36]
    DIRECTION INPUT ;
    USE SIGNAL ;
    ANTENNAGATEAREA 0.109200 ;
    PORT
      LAYER Metal3 ;
        RECT 1399.600 1011.580 1400.000 1011.980 ;
    END
  END num_sv_per_class_flat[36]
  PIN num_sv_per_class_flat[37]
    DIRECTION INPUT ;
    USE SIGNAL ;
    ANTENNAGATEAREA 0.109200 ;
    PORT
      LAYER Metal3 ;
        RECT 1399.600 1003.180 1400.000 1003.580 ;
    END
  END num_sv_per_class_flat[37]
  PIN num_sv_per_class_flat[38]
    DIRECTION INPUT ;
    USE SIGNAL ;
    ANTENNAGATEAREA 0.109200 ;
    PORT
      LAYER Metal2 ;
        RECT 1005.400 1399.600 1005.800 1400.000 ;
    END
  END num_sv_per_class_flat[38]
  PIN num_sv_per_class_flat[39]
    DIRECTION INPUT ;
    USE SIGNAL ;
    ANTENNAGATEAREA 0.109200 ;
    PORT
      LAYER Metal2 ;
        RECT 957.400 1399.600 957.800 1400.000 ;
    END
  END num_sv_per_class_flat[39]
  PIN num_sv_per_class_flat[3]
    DIRECTION INPUT ;
    USE SIGNAL ;
    ANTENNAGATEAREA 0.109200 ;
    PORT
      LAYER Metal3 ;
        RECT 1399.600 1034.260 1400.000 1034.660 ;
    END
  END num_sv_per_class_flat[3]
  PIN num_sv_per_class_flat[4]
    DIRECTION INPUT ;
    USE SIGNAL ;
    ANTENNAGATEAREA 0.109200 ;
    PORT
      LAYER Metal3 ;
        RECT 1399.600 991.420 1400.000 991.820 ;
    END
  END num_sv_per_class_flat[4]
  PIN num_sv_per_class_flat[5]
    DIRECTION INPUT ;
    USE SIGNAL ;
    ANTENNAGATEAREA 0.109200 ;
    PORT
      LAYER Metal3 ;
        RECT 1399.600 985.540 1400.000 985.940 ;
    END
  END num_sv_per_class_flat[5]
  PIN num_sv_per_class_flat[6]
    DIRECTION INPUT ;
    USE SIGNAL ;
    ANTENNAGATEAREA 0.109200 ;
    PORT
      LAYER Metal2 ;
        RECT 939.160 1399.600 939.560 1400.000 ;
    END
  END num_sv_per_class_flat[6]
  PIN num_sv_per_class_flat[7]
    DIRECTION INPUT ;
    USE SIGNAL ;
    ANTENNAGATEAREA 0.109200 ;
    PORT
      LAYER Metal2 ;
        RECT 936.280 1399.600 936.680 1400.000 ;
    END
  END num_sv_per_class_flat[7]
  PIN num_sv_per_class_flat[8]
    DIRECTION INPUT ;
    USE SIGNAL ;
    ANTENNAGATEAREA 0.109200 ;
    PORT
      LAYER Metal2 ;
        RECT 1008.280 1399.600 1008.680 1400.000 ;
    END
  END num_sv_per_class_flat[8]
  PIN num_sv_per_class_flat[9]
    DIRECTION INPUT ;
    USE SIGNAL ;
    ANTENNAGATEAREA 0.109200 ;
    PORT
      LAYER Metal2 ;
        RECT 1003.480 1399.600 1003.880 1400.000 ;
    END
  END num_sv_per_class_flat[9]
  PIN param_addr[0]
    DIRECTION INPUT ;
    USE SIGNAL ;
    ANTENNAGATEAREA 0.109200 ;
    PORT
      LAYER Metal2 ;
        RECT 1108.120 1399.600 1108.520 1400.000 ;
    END
  END param_addr[0]
  PIN param_addr[1]
    DIRECTION INPUT ;
    USE SIGNAL ;
    ANTENNAGATEAREA 0.109200 ;
    PORT
      LAYER Metal2 ;
        RECT 1107.160 1399.600 1107.560 1400.000 ;
    END
  END param_addr[1]
  PIN param_addr[2]
    DIRECTION INPUT ;
    USE SIGNAL ;
    ANTENNAGATEAREA 0.109200 ;
    PORT
      LAYER Metal2 ;
        RECT 1109.080 1399.600 1109.480 1400.000 ;
    END
  END param_addr[2]
  PIN param_data[0]
    DIRECTION INPUT ;
    USE SIGNAL ;
    ANTENNAGATEAREA 0.109200 ;
    PORT
      LAYER Metal2 ;
        RECT 1181.080 1399.600 1181.480 1400.000 ;
    END
  END param_data[0]
  PIN param_data[10]
    DIRECTION INPUT ;
    USE SIGNAL ;
    ANTENNAGATEAREA 0.109200 ;
    PORT
      LAYER Metal2 ;
        RECT 1152.280 1399.600 1152.680 1400.000 ;
    END
  END param_data[10]
  PIN param_data[11]
    DIRECTION INPUT ;
    USE SIGNAL ;
    ANTENNAGATEAREA 0.109200 ;
    PORT
      LAYER Metal2 ;
        RECT 1118.680 1399.600 1119.080 1400.000 ;
    END
  END param_data[11]
  PIN param_data[12]
    DIRECTION INPUT ;
    USE SIGNAL ;
    ANTENNAGATEAREA 0.109200 ;
    PORT
      LAYER Metal2 ;
        RECT 1116.760 1399.600 1117.160 1400.000 ;
    END
  END param_data[12]
  PIN param_data[13]
    DIRECTION INPUT ;
    USE SIGNAL ;
    ANTENNAGATEAREA 0.109200 ;
    PORT
      LAYER Metal2 ;
        RECT 1074.520 1399.600 1074.920 1400.000 ;
    END
  END param_data[13]
  PIN param_data[14]
    DIRECTION INPUT ;
    USE SIGNAL ;
    ANTENNAGATEAREA 0.109200 ;
    PORT
      LAYER Metal2 ;
        RECT 1079.320 1399.600 1079.720 1400.000 ;
    END
  END param_data[14]
  PIN param_data[15]
    DIRECTION INPUT ;
    USE SIGNAL ;
    ANTENNAGATEAREA 0.109200 ;
    PORT
      LAYER Metal2 ;
        RECT 1076.440 1399.600 1076.840 1400.000 ;
    END
  END param_data[15]
  PIN param_data[1]
    DIRECTION INPUT ;
    USE SIGNAL ;
    ANTENNAGATEAREA 0.109200 ;
    PORT
      LAYER Metal2 ;
        RECT 1204.120 1399.600 1204.520 1400.000 ;
    END
  END param_data[1]
  PIN param_data[2]
    DIRECTION INPUT ;
    USE SIGNAL ;
    ANTENNAGATEAREA 0.109200 ;
    PORT
      LAYER Metal3 ;
        RECT 1399.600 1245.940 1400.000 1246.340 ;
    END
  END param_data[2]
  PIN param_data[3]
    DIRECTION INPUT ;
    USE SIGNAL ;
    ANTENNAGATEAREA 0.109200 ;
    PORT
      LAYER Metal2 ;
        RECT 1166.680 1399.600 1167.080 1400.000 ;
    END
  END param_data[3]
  PIN param_data[4]
    DIRECTION INPUT ;
    USE SIGNAL ;
    ANTENNAGATEAREA 0.109200 ;
    PORT
      LAYER Metal2 ;
        RECT 1180.120 1399.600 1180.520 1400.000 ;
    END
  END param_data[4]
  PIN param_data[5]
    DIRECTION INPUT ;
    USE SIGNAL ;
    ANTENNAGATEAREA 0.109200 ;
    PORT
      LAYER Metal3 ;
        RECT 1399.600 1179.580 1400.000 1179.980 ;
    END
  END param_data[5]
  PIN param_data[6]
    DIRECTION INPUT ;
    USE SIGNAL ;
    ANTENNAGATEAREA 0.109200 ;
    PORT
      LAYER Metal3 ;
        RECT 1399.600 1116.580 1400.000 1116.980 ;
    END
  END param_data[6]
  PIN param_data[7]
    DIRECTION INPUT ;
    USE SIGNAL ;
    ANTENNAGATEAREA 0.109200 ;
    PORT
      LAYER Metal3 ;
        RECT 1399.600 1119.100 1400.000 1119.500 ;
    END
  END param_data[7]
  PIN param_data[8]
    DIRECTION INPUT ;
    USE SIGNAL ;
    ANTENNAGATEAREA 0.109200 ;
    PORT
      LAYER Metal2 ;
        RECT 1183.000 1399.600 1183.400 1400.000 ;
    END
  END param_data[8]
  PIN param_data[9]
    DIRECTION INPUT ;
    USE SIGNAL ;
    ANTENNAGATEAREA 0.109200 ;
    PORT
      LAYER Metal2 ;
        RECT 1151.320 1399.600 1151.720 1400.000 ;
    END
  END param_data[9]
  PIN param_write_en
    DIRECTION INPUT ;
    USE SIGNAL ;
    ANTENNAGATEAREA 0.109200 ;
    PORT
      LAYER Metal2 ;
        RECT 1106.200 1399.600 1106.600 1400.000 ;
    END
  END param_write_en
  PIN ram_addr[0]
    DIRECTION OUTPUT ;
    USE SIGNAL ;
    ANTENNADIFFAREA 0.708600 ;
    PORT
      LAYER Metal3 ;
        RECT 0.000 972.100 0.400 972.500 ;
    END
  END ram_addr[0]
  PIN ram_addr[10]
    DIRECTION OUTPUT ;
    USE SIGNAL ;
    ANTENNADIFFAREA 0.708600 ;
    PORT
      LAYER Metal2 ;
        RECT 971.800 1399.600 972.200 1400.000 ;
    END
  END ram_addr[10]
  PIN ram_addr[11]
    DIRECTION OUTPUT ;
    USE SIGNAL ;
    ANTENNADIFFAREA 0.708600 ;
    PORT
      LAYER Metal2 ;
        RECT 973.720 1399.600 974.120 1400.000 ;
    END
  END ram_addr[11]
  PIN ram_addr[12]
    DIRECTION OUTPUT ;
    USE SIGNAL ;
    ANTENNADIFFAREA 0.708600 ;
    PORT
      LAYER Metal2 ;
        RECT 975.640 1399.600 976.040 1400.000 ;
    END
  END ram_addr[12]
  PIN ram_addr[13]
    DIRECTION OUTPUT ;
    USE SIGNAL ;
    ANTENNADIFFAREA 0.708600 ;
    PORT
      LAYER Metal2 ;
        RECT 974.680 1399.600 975.080 1400.000 ;
    END
  END ram_addr[13]
  PIN ram_addr[14]
    DIRECTION OUTPUT ;
    USE SIGNAL ;
    ANTENNADIFFAREA 0.708600 ;
    PORT
      LAYER Metal2 ;
        RECT 972.760 1399.600 973.160 1400.000 ;
    END
  END ram_addr[14]
  PIN ram_addr[15]
    DIRECTION OUTPUT ;
    USE SIGNAL ;
    ANTENNADIFFAREA 0.708600 ;
    PORT
      LAYER Metal2 ;
        RECT 967.960 1399.600 968.360 1400.000 ;
    END
  END ram_addr[15]
  PIN ram_addr[16]
    DIRECTION OUTPUT ;
    USE SIGNAL ;
    ANTENNADIFFAREA 0.708600 ;
    PORT
      LAYER Metal2 ;
        RECT 942.040 1399.600 942.440 1400.000 ;
    END
  END ram_addr[16]
  PIN ram_addr[17]
    DIRECTION OUTPUT ;
    USE SIGNAL ;
    ANTENNADIFFAREA 0.708600 ;
    PORT
      LAYER Metal2 ;
        RECT 949.720 1399.600 950.120 1400.000 ;
    END
  END ram_addr[17]
  PIN ram_addr[18]
    DIRECTION OUTPUT ;
    USE SIGNAL ;
    ANTENNADIFFAREA 0.708600 ;
    PORT
      LAYER Metal2 ;
        RECT 948.760 1399.600 949.160 1400.000 ;
    END
  END ram_addr[18]
  PIN ram_addr[1]
    DIRECTION OUTPUT ;
    USE SIGNAL ;
    ANTENNADIFFAREA 0.708600 ;
    PORT
      LAYER Metal3 ;
        RECT 0.000 970.420 0.400 970.820 ;
    END
  END ram_addr[1]
  PIN ram_addr[2]
    DIRECTION OUTPUT ;
    USE SIGNAL ;
    ANTENNADIFFAREA 0.708600 ;
    PORT
      LAYER Metal3 ;
        RECT 0.000 958.660 0.400 959.060 ;
    END
  END ram_addr[2]
  PIN ram_addr[3]
    DIRECTION OUTPUT ;
    USE SIGNAL ;
    ANTENNADIFFAREA 0.708600 ;
    PORT
      LAYER Metal3 ;
        RECT 0.000 951.940 0.400 952.340 ;
    END
  END ram_addr[3]
  PIN ram_addr[4]
    DIRECTION OUTPUT ;
    USE SIGNAL ;
    ANTENNADIFFAREA 0.708600 ;
    PORT
      LAYER Metal3 ;
        RECT 0.000 938.500 0.400 938.900 ;
    END
  END ram_addr[4]
  PIN ram_addr[5]
    DIRECTION OUTPUT ;
    USE SIGNAL ;
    ANTENNADIFFAREA 0.708600 ;
    PORT
      LAYER Metal3 ;
        RECT 0.000 952.780 0.400 953.180 ;
    END
  END ram_addr[5]
  PIN ram_addr[6]
    DIRECTION OUTPUT ;
    USE SIGNAL ;
    ANTENNADIFFAREA 0.708600 ;
    PORT
      LAYER Metal3 ;
        RECT 0.000 946.900 0.400 947.300 ;
    END
  END ram_addr[6]
  PIN ram_addr[7]
    DIRECTION OUTPUT ;
    USE SIGNAL ;
    ANTENNADIFFAREA 0.708600 ;
    PORT
      LAYER Metal3 ;
        RECT 0.000 971.260 0.400 971.660 ;
    END
  END ram_addr[7]
  PIN ram_addr[8]
    DIRECTION OUTPUT ;
    USE SIGNAL ;
    ANTENNADIFFAREA 0.708600 ;
    PORT
      LAYER Metal2 ;
        RECT 967.000 1399.600 967.400 1400.000 ;
    END
  END ram_addr[8]
  PIN ram_addr[9]
    DIRECTION OUTPUT ;
    USE SIGNAL ;
    ANTENNADIFFAREA 0.708600 ;
    PORT
      LAYER Metal2 ;
        RECT 965.080 1399.600 965.480 1400.000 ;
    END
  END ram_addr[9]
  PIN ram_rdata[0]
    DIRECTION INPUT ;
    USE SIGNAL ;
    ANTENNAGATEAREA 0.109200 ;
    PORT
      LAYER Metal3 ;
        RECT 0.000 1364.380 0.400 1364.780 ;
    END
  END ram_rdata[0]
  PIN ram_rdata[10]
    DIRECTION INPUT ;
    USE SIGNAL ;
    ANTENNAGATEAREA 0.109200 ;
    PORT
      LAYER Metal3 ;
        RECT 0.000 1181.260 0.400 1181.660 ;
    END
  END ram_rdata[10]
  PIN ram_rdata[11]
    DIRECTION INPUT ;
    USE SIGNAL ;
    ANTENNAGATEAREA 0.109200 ;
    PORT
      LAYER Metal3 ;
        RECT 0.000 1351.780 0.400 1352.180 ;
    END
  END ram_rdata[11]
  PIN ram_rdata[12]
    DIRECTION INPUT ;
    USE SIGNAL ;
    ANTENNAGATEAREA 0.109200 ;
    PORT
      LAYER Metal3 ;
        RECT 0.000 1229.140 0.400 1229.540 ;
    END
  END ram_rdata[12]
  PIN ram_rdata[13]
    DIRECTION INPUT ;
    USE SIGNAL ;
    ANTENNAGATEAREA 0.109200 ;
    PORT
      LAYER Metal3 ;
        RECT 0.000 1228.300 0.400 1228.700 ;
    END
  END ram_rdata[13]
  PIN ram_rdata[14]
    DIRECTION INPUT ;
    USE SIGNAL ;
    ANTENNAGATEAREA 0.109200 ;
    PORT
      LAYER Metal3 ;
        RECT 0.000 1191.340 0.400 1191.740 ;
    END
  END ram_rdata[14]
  PIN ram_rdata[15]
    DIRECTION INPUT ;
    USE SIGNAL ;
    ANTENNAGATEAREA 0.109200 ;
    PORT
      LAYER Metal3 ;
        RECT 0.000 1361.860 0.400 1362.260 ;
    END
  END ram_rdata[15]
  PIN ram_rdata[1]
    DIRECTION INPUT ;
    USE SIGNAL ;
    ANTENNAGATEAREA 0.109200 ;
    PORT
      LAYER Metal3 ;
        RECT 0.000 1350.940 0.400 1351.340 ;
    END
  END ram_rdata[1]
  PIN ram_rdata[2]
    DIRECTION INPUT ;
    USE SIGNAL ;
    ANTENNAGATEAREA 0.109200 ;
    PORT
      LAYER Metal3 ;
        RECT 0.000 1363.540 0.400 1363.940 ;
    END
  END ram_rdata[2]
  PIN ram_rdata[3]
    DIRECTION INPUT ;
    USE SIGNAL ;
    ANTENNAGATEAREA 0.109200 ;
    PORT
      LAYER Metal3 ;
        RECT 0.000 1227.460 0.400 1227.860 ;
    END
  END ram_rdata[3]
  PIN ram_rdata[4]
    DIRECTION INPUT ;
    USE SIGNAL ;
    ANTENNAGATEAREA 0.109200 ;
    PORT
      LAYER Metal3 ;
        RECT 0.000 1042.660 0.400 1043.060 ;
    END
  END ram_rdata[4]
  PIN ram_rdata[5]
    DIRECTION INPUT ;
    USE SIGNAL ;
    ANTENNAGATEAREA 0.109200 ;
    PORT
      LAYER Metal3 ;
        RECT 0.000 1061.140 0.400 1061.540 ;
    END
  END ram_rdata[5]
  PIN ram_rdata[6]
    DIRECTION INPUT ;
    USE SIGNAL ;
    ANTENNAGATEAREA 0.109200 ;
    PORT
      LAYER Metal3 ;
        RECT 0.000 1359.340 0.400 1359.740 ;
    END
  END ram_rdata[6]
  PIN ram_rdata[7]
    DIRECTION INPUT ;
    USE SIGNAL ;
    ANTENNAGATEAREA 0.109200 ;
    PORT
      LAYER Metal3 ;
        RECT 0.000 1170.340 0.400 1170.740 ;
    END
  END ram_rdata[7]
  PIN ram_rdata[8]
    DIRECTION INPUT ;
    USE SIGNAL ;
    ANTENNAGATEAREA 0.109200 ;
    PORT
      LAYER Metal2 ;
        RECT 25.240 0.000 25.640 0.400 ;
    END
  END ram_rdata[8]
  PIN ram_rdata[9]
    DIRECTION INPUT ;
    USE SIGNAL ;
    ANTENNAGATEAREA 0.109200 ;
    PORT
      LAYER Metal3 ;
        RECT 0.000 1329.940 0.400 1330.340 ;
    END
  END ram_rdata[9]
  PIN ram_ren
    DIRECTION OUTPUT ;
    USE SIGNAL ;
    ANTENNADIFFAREA 0.708600 ;
    PORT
      LAYER Metal3 ;
        RECT 0.000 977.140 0.400 977.540 ;
    END
  END ram_ren
  PIN rst_n
    DIRECTION INPUT ;
    USE SIGNAL ;
    ANTENNAGATEAREA 0.109200 ;
    PORT
      LAYER Metal3 ;
        RECT 1399.600 30.460 1400.000 30.860 ;
    END
  END rst_n
  PIN sample_rdy
    DIRECTION OUTPUT ;
    USE SIGNAL ;
    ANTENNADIFFAREA 0.708600 ;
    PORT
      LAYER Metal2 ;
        RECT 953.560 1399.600 953.960 1400.000 ;
    END
  END sample_rdy
  PIN start
    DIRECTION INPUT ;
    USE SIGNAL ;
    ANTENNAGATEAREA 0.109200 ;
    PORT
      LAYER Metal2 ;
        RECT 947.800 1399.600 948.200 1400.000 ;
    END
  END start
  PIN vbatt_ok
    DIRECTION INPUT ;
    USE SIGNAL ;
    ANTENNAGATEAREA 0.109200 ;
    PORT
      LAYER Metal2 ;
        RECT 926.680 1399.600 927.080 1400.000 ;
    END
  END vbatt_ok
  PIN vbatt_warn
    DIRECTION INPUT ;
    USE SIGNAL ;
    ANTENNAGATEAREA 0.109200 ;
    PORT
      LAYER Metal2 ;
        RECT 922.840 1399.600 923.240 1400.000 ;
    END
  END vbatt_warn
  OBS
      LAYER GatPoly ;
        RECT 5.760 14.970 1393.920 1383.630 ;
      LAYER Metal1 ;
        RECT 5.760 14.900 1393.920 1383.700 ;
      LAYER Metal2 ;
        RECT 5.175 1399.390 729.670 1399.600 ;
        RECT 730.490 1399.390 730.630 1399.600 ;
        RECT 731.450 1399.390 736.390 1399.600 ;
        RECT 737.210 1399.390 737.350 1399.600 ;
        RECT 738.170 1399.390 738.310 1399.600 ;
        RECT 739.130 1399.390 739.270 1399.600 ;
        RECT 740.090 1399.390 743.110 1399.600 ;
        RECT 743.930 1399.390 744.070 1399.600 ;
        RECT 744.890 1399.390 745.030 1399.600 ;
        RECT 745.850 1399.390 745.990 1399.600 ;
        RECT 746.810 1399.390 919.750 1399.600 ;
        RECT 920.570 1399.390 920.710 1399.600 ;
        RECT 921.530 1399.390 921.670 1399.600 ;
        RECT 922.490 1399.390 922.630 1399.600 ;
        RECT 923.450 1399.390 923.590 1399.600 ;
        RECT 924.410 1399.390 924.550 1399.600 ;
        RECT 925.370 1399.390 925.510 1399.600 ;
        RECT 926.330 1399.390 926.470 1399.600 ;
        RECT 927.290 1399.390 927.430 1399.600 ;
        RECT 928.250 1399.390 928.390 1399.600 ;
        RECT 929.210 1399.390 930.310 1399.600 ;
        RECT 931.130 1399.390 931.270 1399.600 ;
        RECT 932.090 1399.390 935.110 1399.600 ;
        RECT 935.930 1399.390 936.070 1399.600 ;
        RECT 936.890 1399.390 938.950 1399.600 ;
        RECT 939.770 1399.390 940.870 1399.600 ;
        RECT 941.690 1399.390 941.830 1399.600 ;
        RECT 942.650 1399.390 942.790 1399.600 ;
        RECT 943.610 1399.390 943.750 1399.600 ;
        RECT 944.570 1399.390 944.710 1399.600 ;
        RECT 945.530 1399.390 945.670 1399.600 ;
        RECT 946.490 1399.390 946.630 1399.600 ;
        RECT 947.450 1399.390 947.590 1399.600 ;
        RECT 948.410 1399.390 948.550 1399.600 ;
        RECT 949.370 1399.390 949.510 1399.600 ;
        RECT 950.330 1399.390 950.470 1399.600 ;
        RECT 951.290 1399.390 951.430 1399.600 ;
        RECT 952.250 1399.390 952.390 1399.600 ;
        RECT 953.210 1399.390 953.350 1399.600 ;
        RECT 954.170 1399.390 954.310 1399.600 ;
        RECT 955.130 1399.390 956.230 1399.600 ;
        RECT 957.050 1399.390 957.190 1399.600 ;
        RECT 958.010 1399.390 960.070 1399.600 ;
        RECT 960.890 1399.390 961.030 1399.600 ;
        RECT 961.850 1399.390 961.990 1399.600 ;
        RECT 962.810 1399.390 962.950 1399.600 ;
        RECT 963.770 1399.390 963.910 1399.600 ;
        RECT 964.730 1399.390 964.870 1399.600 ;
        RECT 965.690 1399.390 965.830 1399.600 ;
        RECT 966.650 1399.390 966.790 1399.600 ;
        RECT 967.610 1399.390 967.750 1399.600 ;
        RECT 968.570 1399.390 968.710 1399.600 ;
        RECT 969.530 1399.390 969.670 1399.600 ;
        RECT 970.490 1399.390 970.630 1399.600 ;
        RECT 971.450 1399.390 971.590 1399.600 ;
        RECT 972.410 1399.390 972.550 1399.600 ;
        RECT 973.370 1399.390 973.510 1399.600 ;
        RECT 974.330 1399.390 974.470 1399.600 ;
        RECT 975.290 1399.390 975.430 1399.600 ;
        RECT 976.250 1399.390 976.390 1399.600 ;
        RECT 977.210 1399.390 977.350 1399.600 ;
        RECT 978.170 1399.390 978.310 1399.600 ;
        RECT 979.130 1399.390 979.270 1399.600 ;
        RECT 980.090 1399.390 980.230 1399.600 ;
        RECT 981.050 1399.390 981.190 1399.600 ;
        RECT 982.010 1399.390 985.030 1399.600 ;
        RECT 985.850 1399.390 985.990 1399.600 ;
        RECT 986.810 1399.390 987.910 1399.600 ;
        RECT 988.730 1399.390 990.790 1399.600 ;
        RECT 991.610 1399.390 992.710 1399.600 ;
        RECT 993.530 1399.390 994.630 1399.600 ;
        RECT 995.450 1399.390 995.590 1399.600 ;
        RECT 996.410 1399.390 996.550 1399.600 ;
        RECT 997.370 1399.390 997.510 1399.600 ;
        RECT 998.330 1399.390 998.470 1399.600 ;
        RECT 999.290 1399.390 999.430 1399.600 ;
        RECT 1000.250 1399.390 1000.390 1399.600 ;
        RECT 1001.210 1399.390 1001.350 1399.600 ;
        RECT 1002.170 1399.390 1002.310 1399.600 ;
        RECT 1003.130 1399.390 1003.270 1399.600 ;
        RECT 1004.090 1399.390 1004.230 1399.600 ;
        RECT 1005.050 1399.390 1005.190 1399.600 ;
        RECT 1006.010 1399.390 1006.150 1399.600 ;
        RECT 1006.970 1399.390 1007.110 1399.600 ;
        RECT 1007.930 1399.390 1008.070 1399.600 ;
        RECT 1008.890 1399.390 1009.030 1399.600 ;
        RECT 1009.850 1399.390 1009.990 1399.600 ;
        RECT 1010.810 1399.390 1010.950 1399.600 ;
        RECT 1011.770 1399.390 1011.910 1399.600 ;
        RECT 1012.730 1399.390 1012.870 1399.600 ;
        RECT 1013.690 1399.390 1019.590 1399.600 ;
        RECT 1020.410 1399.390 1020.550 1399.600 ;
        RECT 1021.370 1399.390 1021.510 1399.600 ;
        RECT 1022.330 1399.390 1023.430 1399.600 ;
        RECT 1024.250 1399.390 1025.350 1399.600 ;
        RECT 1026.170 1399.390 1028.230 1399.600 ;
        RECT 1029.050 1399.390 1029.190 1399.600 ;
        RECT 1030.010 1399.390 1030.150 1399.600 ;
        RECT 1030.970 1399.390 1034.950 1399.600 ;
        RECT 1035.770 1399.390 1036.870 1399.600 ;
        RECT 1037.690 1399.390 1037.830 1399.600 ;
        RECT 1038.650 1399.390 1040.710 1399.600 ;
        RECT 1041.530 1399.390 1041.670 1399.600 ;
        RECT 1042.490 1399.390 1043.590 1399.600 ;
        RECT 1044.410 1399.390 1044.550 1399.600 ;
        RECT 1045.370 1399.390 1045.510 1399.600 ;
        RECT 1046.330 1399.390 1046.470 1399.600 ;
        RECT 1047.290 1399.390 1049.350 1399.600 ;
        RECT 1050.170 1399.390 1050.310 1399.600 ;
        RECT 1051.130 1399.390 1051.270 1399.600 ;
        RECT 1052.090 1399.390 1052.230 1399.600 ;
        RECT 1053.050 1399.390 1053.190 1399.600 ;
        RECT 1054.010 1399.390 1054.150 1399.600 ;
        RECT 1054.970 1399.390 1055.110 1399.600 ;
        RECT 1055.930 1399.390 1056.070 1399.600 ;
        RECT 1056.890 1399.390 1057.990 1399.600 ;
        RECT 1058.810 1399.390 1058.950 1399.600 ;
        RECT 1059.770 1399.390 1063.750 1399.600 ;
        RECT 1064.570 1399.390 1064.710 1399.600 ;
        RECT 1065.530 1399.390 1066.630 1399.600 ;
        RECT 1067.450 1399.390 1070.470 1399.600 ;
        RECT 1071.290 1399.390 1071.430 1399.600 ;
        RECT 1072.250 1399.390 1074.310 1399.600 ;
        RECT 1075.130 1399.390 1075.270 1399.600 ;
        RECT 1076.090 1399.390 1076.230 1399.600 ;
        RECT 1077.050 1399.390 1077.190 1399.600 ;
        RECT 1078.010 1399.390 1078.150 1399.600 ;
        RECT 1078.970 1399.390 1079.110 1399.600 ;
        RECT 1079.930 1399.390 1080.070 1399.600 ;
        RECT 1080.890 1399.390 1081.030 1399.600 ;
        RECT 1081.850 1399.390 1083.910 1399.600 ;
        RECT 1084.730 1399.390 1084.870 1399.600 ;
        RECT 1085.690 1399.390 1085.830 1399.600 ;
        RECT 1086.650 1399.390 1086.790 1399.600 ;
        RECT 1087.610 1399.390 1087.750 1399.600 ;
        RECT 1088.570 1399.390 1088.710 1399.600 ;
        RECT 1089.530 1399.390 1091.590 1399.600 ;
        RECT 1092.410 1399.390 1096.390 1399.600 ;
        RECT 1097.210 1399.390 1097.350 1399.600 ;
        RECT 1098.170 1399.390 1098.310 1399.600 ;
        RECT 1099.130 1399.390 1099.270 1399.600 ;
        RECT 1100.090 1399.390 1100.230 1399.600 ;
        RECT 1101.050 1399.390 1101.190 1399.600 ;
        RECT 1102.010 1399.390 1102.150 1399.600 ;
        RECT 1102.970 1399.390 1103.110 1399.600 ;
        RECT 1103.930 1399.390 1104.070 1399.600 ;
        RECT 1104.890 1399.390 1105.030 1399.600 ;
        RECT 1105.850 1399.390 1105.990 1399.600 ;
        RECT 1106.810 1399.390 1106.950 1399.600 ;
        RECT 1107.770 1399.390 1107.910 1399.600 ;
        RECT 1108.730 1399.390 1108.870 1399.600 ;
        RECT 1109.690 1399.390 1109.830 1399.600 ;
        RECT 1110.650 1399.390 1110.790 1399.600 ;
        RECT 1111.610 1399.390 1111.750 1399.600 ;
        RECT 1112.570 1399.390 1112.710 1399.600 ;
        RECT 1113.530 1399.390 1116.550 1399.600 ;
        RECT 1117.370 1399.390 1117.510 1399.600 ;
        RECT 1118.330 1399.390 1118.470 1399.600 ;
        RECT 1119.290 1399.390 1119.430 1399.600 ;
        RECT 1120.250 1399.390 1120.390 1399.600 ;
        RECT 1121.210 1399.390 1125.190 1399.600 ;
        RECT 1126.010 1399.390 1126.150 1399.600 ;
        RECT 1126.970 1399.390 1128.070 1399.600 ;
        RECT 1128.890 1399.390 1129.990 1399.600 ;
        RECT 1130.810 1399.390 1130.950 1399.600 ;
        RECT 1131.770 1399.390 1131.910 1399.600 ;
        RECT 1132.730 1399.390 1132.870 1399.600 ;
        RECT 1133.690 1399.390 1133.830 1399.600 ;
        RECT 1134.650 1399.390 1134.790 1399.600 ;
        RECT 1135.610 1399.390 1135.750 1399.600 ;
        RECT 1136.570 1399.390 1136.710 1399.600 ;
        RECT 1137.530 1399.390 1137.670 1399.600 ;
        RECT 1138.490 1399.390 1140.550 1399.600 ;
        RECT 1141.370 1399.390 1146.310 1399.600 ;
        RECT 1147.130 1399.390 1147.270 1399.600 ;
        RECT 1148.090 1399.390 1148.230 1399.600 ;
        RECT 1149.050 1399.390 1149.190 1399.600 ;
        RECT 1150.010 1399.390 1150.150 1399.600 ;
        RECT 1150.970 1399.390 1151.110 1399.600 ;
        RECT 1151.930 1399.390 1152.070 1399.600 ;
        RECT 1152.890 1399.390 1153.030 1399.600 ;
        RECT 1153.850 1399.390 1153.990 1399.600 ;
        RECT 1154.810 1399.390 1154.950 1399.600 ;
        RECT 1155.770 1399.390 1155.910 1399.600 ;
        RECT 1156.730 1399.390 1156.870 1399.600 ;
        RECT 1157.690 1399.390 1157.830 1399.600 ;
        RECT 1158.650 1399.390 1160.710 1399.600 ;
        RECT 1161.530 1399.390 1164.550 1399.600 ;
        RECT 1165.370 1399.390 1165.510 1399.600 ;
        RECT 1166.330 1399.390 1166.470 1399.600 ;
        RECT 1167.290 1399.390 1168.390 1399.600 ;
        RECT 1169.210 1399.390 1179.910 1399.600 ;
        RECT 1180.730 1399.390 1180.870 1399.600 ;
        RECT 1181.690 1399.390 1182.790 1399.600 ;
        RECT 1183.610 1399.390 1203.910 1399.600 ;
        RECT 1204.730 1399.390 1204.870 1399.600 ;
        RECT 1205.690 1399.390 1399.785 1399.600 ;
        RECT 5.175 0.610 1399.785 1399.390 ;
        RECT 5.175 0.100 25.030 0.610 ;
        RECT 25.850 0.100 472.390 0.610 ;
        RECT 473.210 0.100 478.150 0.610 ;
        RECT 478.970 0.100 1399.785 0.610 ;
      LAYER Metal3 ;
        RECT 0.400 1364.990 1399.900 1399.540 ;
        RECT 0.610 1364.170 1399.900 1364.990 ;
        RECT 0.400 1364.150 1399.900 1364.170 ;
        RECT 0.610 1363.330 1399.900 1364.150 ;
        RECT 0.400 1362.470 1399.900 1363.330 ;
        RECT 0.610 1361.650 1399.900 1362.470 ;
        RECT 0.400 1359.950 1399.900 1361.650 ;
        RECT 0.610 1359.130 1399.900 1359.950 ;
        RECT 0.400 1352.390 1399.900 1359.130 ;
        RECT 0.610 1351.570 1399.900 1352.390 ;
        RECT 0.400 1351.550 1399.900 1351.570 ;
        RECT 0.610 1350.730 1399.900 1351.550 ;
        RECT 0.400 1330.550 1399.900 1350.730 ;
        RECT 0.610 1329.730 1399.900 1330.550 ;
        RECT 0.400 1246.550 1399.900 1329.730 ;
        RECT 0.400 1245.730 1399.390 1246.550 ;
        RECT 0.400 1231.430 1399.900 1245.730 ;
        RECT 0.400 1230.610 1399.390 1231.430 ;
        RECT 0.400 1230.590 1399.900 1230.610 ;
        RECT 0.400 1229.770 1399.390 1230.590 ;
        RECT 0.400 1229.750 1399.900 1229.770 ;
        RECT 0.610 1228.930 1399.390 1229.750 ;
        RECT 0.400 1228.910 1399.900 1228.930 ;
        RECT 0.610 1228.090 1399.390 1228.910 ;
        RECT 0.400 1228.070 1399.900 1228.090 ;
        RECT 0.610 1227.250 1399.900 1228.070 ;
        RECT 0.400 1225.550 1399.900 1227.250 ;
        RECT 0.400 1224.730 1399.390 1225.550 ;
        RECT 0.400 1224.710 1399.900 1224.730 ;
        RECT 0.400 1223.890 1399.390 1224.710 ;
        RECT 0.400 1223.030 1399.900 1223.890 ;
        RECT 0.400 1222.210 1399.390 1223.030 ;
        RECT 0.400 1219.670 1399.900 1222.210 ;
        RECT 0.400 1218.850 1399.390 1219.670 ;
        RECT 0.400 1217.990 1399.900 1218.850 ;
        RECT 0.400 1217.170 1399.390 1217.990 ;
        RECT 0.400 1204.550 1399.900 1217.170 ;
        RECT 0.400 1203.730 1399.390 1204.550 ;
        RECT 0.400 1202.030 1399.900 1203.730 ;
        RECT 0.400 1201.210 1399.390 1202.030 ;
        RECT 0.400 1191.950 1399.900 1201.210 ;
        RECT 0.610 1191.130 1399.390 1191.950 ;
        RECT 0.400 1191.110 1399.900 1191.130 ;
        RECT 0.400 1190.290 1399.390 1191.110 ;
        RECT 0.400 1189.430 1399.900 1190.290 ;
        RECT 0.400 1188.610 1399.390 1189.430 ;
        RECT 0.400 1188.590 1399.900 1188.610 ;
        RECT 0.400 1187.770 1399.390 1188.590 ;
        RECT 0.400 1181.870 1399.900 1187.770 ;
        RECT 0.610 1181.050 1399.900 1181.870 ;
        RECT 0.400 1180.190 1399.900 1181.050 ;
        RECT 0.400 1179.370 1399.390 1180.190 ;
        RECT 0.400 1179.350 1399.900 1179.370 ;
        RECT 0.400 1178.530 1399.390 1179.350 ;
        RECT 0.400 1178.510 1399.900 1178.530 ;
        RECT 0.400 1177.690 1399.390 1178.510 ;
        RECT 0.400 1174.310 1399.900 1177.690 ;
        RECT 0.400 1173.490 1399.390 1174.310 ;
        RECT 0.400 1171.790 1399.900 1173.490 ;
        RECT 0.400 1170.970 1399.390 1171.790 ;
        RECT 0.400 1170.950 1399.900 1170.970 ;
        RECT 0.610 1170.130 1399.390 1170.950 ;
        RECT 0.400 1156.670 1399.900 1170.130 ;
        RECT 0.400 1155.850 1399.390 1156.670 ;
        RECT 0.400 1154.990 1399.900 1155.850 ;
        RECT 0.400 1154.170 1399.390 1154.990 ;
        RECT 0.400 1152.470 1399.900 1154.170 ;
        RECT 0.400 1151.650 1399.390 1152.470 ;
        RECT 0.400 1145.750 1399.900 1151.650 ;
        RECT 0.400 1144.930 1399.390 1145.750 ;
        RECT 0.400 1144.910 1399.900 1144.930 ;
        RECT 0.400 1144.090 1399.390 1144.910 ;
        RECT 0.400 1142.390 1399.900 1144.090 ;
        RECT 0.400 1141.570 1399.390 1142.390 ;
        RECT 0.400 1130.630 1399.900 1141.570 ;
        RECT 0.400 1129.810 1399.390 1130.630 ;
        RECT 0.400 1129.790 1399.900 1129.810 ;
        RECT 0.400 1128.970 1399.390 1129.790 ;
        RECT 0.400 1128.950 1399.900 1128.970 ;
        RECT 0.400 1128.130 1399.390 1128.950 ;
        RECT 0.400 1128.110 1399.900 1128.130 ;
        RECT 0.400 1127.290 1399.390 1128.110 ;
        RECT 0.400 1125.590 1399.900 1127.290 ;
        RECT 0.400 1124.770 1399.390 1125.590 ;
        RECT 0.400 1122.230 1399.900 1124.770 ;
        RECT 0.400 1121.410 1399.390 1122.230 ;
        RECT 0.400 1120.550 1399.900 1121.410 ;
        RECT 0.400 1119.730 1399.390 1120.550 ;
        RECT 0.400 1119.710 1399.900 1119.730 ;
        RECT 0.400 1118.890 1399.390 1119.710 ;
        RECT 0.400 1117.190 1399.900 1118.890 ;
        RECT 0.400 1116.370 1399.390 1117.190 ;
        RECT 0.400 1116.350 1399.900 1116.370 ;
        RECT 0.400 1115.530 1399.390 1116.350 ;
        RECT 0.400 1115.510 1399.900 1115.530 ;
        RECT 0.400 1114.690 1399.390 1115.510 ;
        RECT 0.400 1113.830 1399.900 1114.690 ;
        RECT 0.400 1113.010 1399.390 1113.830 ;
        RECT 0.400 1110.470 1399.900 1113.010 ;
        RECT 0.400 1109.650 1399.390 1110.470 ;
        RECT 0.400 1108.790 1399.900 1109.650 ;
        RECT 0.400 1107.970 1399.390 1108.790 ;
        RECT 0.400 1107.950 1399.900 1107.970 ;
        RECT 0.400 1107.130 1399.390 1107.950 ;
        RECT 0.400 1107.110 1399.900 1107.130 ;
        RECT 0.400 1106.290 1399.390 1107.110 ;
        RECT 0.400 1105.430 1399.900 1106.290 ;
        RECT 0.400 1104.610 1399.390 1105.430 ;
        RECT 0.400 1100.390 1399.900 1104.610 ;
        RECT 0.400 1099.570 1399.390 1100.390 ;
        RECT 0.400 1098.710 1399.900 1099.570 ;
        RECT 0.400 1097.890 1399.390 1098.710 ;
        RECT 0.400 1096.190 1399.900 1097.890 ;
        RECT 0.400 1095.370 1399.390 1096.190 ;
        RECT 0.400 1086.110 1399.900 1095.370 ;
        RECT 0.400 1085.290 1399.390 1086.110 ;
        RECT 0.400 1082.750 1399.900 1085.290 ;
        RECT 0.400 1081.930 1399.390 1082.750 ;
        RECT 0.400 1079.390 1399.900 1081.930 ;
        RECT 0.400 1078.570 1399.390 1079.390 ;
        RECT 0.400 1077.710 1399.900 1078.570 ;
        RECT 0.400 1076.890 1399.390 1077.710 ;
        RECT 0.400 1066.790 1399.900 1076.890 ;
        RECT 0.400 1065.970 1399.390 1066.790 ;
        RECT 0.400 1061.750 1399.900 1065.970 ;
        RECT 0.610 1060.930 1399.900 1061.750 ;
        RECT 0.400 1060.910 1399.900 1060.930 ;
        RECT 0.400 1060.090 1399.390 1060.910 ;
        RECT 0.400 1059.230 1399.900 1060.090 ;
        RECT 0.400 1058.410 1399.390 1059.230 ;
        RECT 0.400 1058.390 1399.900 1058.410 ;
        RECT 0.400 1057.570 1399.390 1058.390 ;
        RECT 0.400 1056.710 1399.900 1057.570 ;
        RECT 0.400 1055.890 1399.390 1056.710 ;
        RECT 0.400 1043.270 1399.900 1055.890 ;
        RECT 0.610 1042.450 1399.900 1043.270 ;
        RECT 0.400 1040.750 1399.900 1042.450 ;
        RECT 0.400 1039.930 1399.390 1040.750 ;
        RECT 0.400 1038.230 1399.900 1039.930 ;
        RECT 0.400 1037.410 1399.390 1038.230 ;
        RECT 0.400 1034.870 1399.900 1037.410 ;
        RECT 0.400 1034.050 1399.390 1034.870 ;
        RECT 0.400 1030.670 1399.900 1034.050 ;
        RECT 0.400 1029.850 1399.390 1030.670 ;
        RECT 0.400 1024.790 1399.900 1029.850 ;
        RECT 0.400 1023.970 1399.390 1024.790 ;
        RECT 0.400 1021.430 1399.900 1023.970 ;
        RECT 0.400 1020.610 1399.390 1021.430 ;
        RECT 0.400 1016.390 1399.900 1020.610 ;
        RECT 0.400 1015.570 1399.390 1016.390 ;
        RECT 0.400 1014.710 1399.900 1015.570 ;
        RECT 0.400 1013.890 1399.390 1014.710 ;
        RECT 0.400 1013.870 1399.900 1013.890 ;
        RECT 0.400 1013.050 1399.390 1013.870 ;
        RECT 0.400 1013.030 1399.900 1013.050 ;
        RECT 0.400 1012.210 1399.390 1013.030 ;
        RECT 0.400 1012.190 1399.900 1012.210 ;
        RECT 0.400 1011.370 1399.390 1012.190 ;
        RECT 0.400 1011.350 1399.900 1011.370 ;
        RECT 0.400 1010.530 1399.390 1011.350 ;
        RECT 0.400 1010.510 1399.900 1010.530 ;
        RECT 0.400 1009.690 1399.390 1010.510 ;
        RECT 0.400 1003.790 1399.900 1009.690 ;
        RECT 0.400 1002.970 1399.390 1003.790 ;
        RECT 0.400 992.030 1399.900 1002.970 ;
        RECT 0.400 991.210 1399.390 992.030 ;
        RECT 0.400 991.190 1399.900 991.210 ;
        RECT 0.400 990.370 1399.390 991.190 ;
        RECT 0.400 986.990 1399.900 990.370 ;
        RECT 0.400 986.170 1399.390 986.990 ;
        RECT 0.400 986.150 1399.900 986.170 ;
        RECT 0.400 985.330 1399.390 986.150 ;
        RECT 0.400 985.310 1399.900 985.330 ;
        RECT 0.400 984.490 1399.390 985.310 ;
        RECT 0.400 981.950 1399.900 984.490 ;
        RECT 0.400 981.130 1399.390 981.950 ;
        RECT 0.400 979.430 1399.900 981.130 ;
        RECT 0.400 978.610 1399.390 979.430 ;
        RECT 0.400 977.750 1399.900 978.610 ;
        RECT 0.610 976.930 1399.390 977.750 ;
        RECT 0.400 976.910 1399.900 976.930 ;
        RECT 0.400 976.090 1399.390 976.910 ;
        RECT 0.400 976.070 1399.900 976.090 ;
        RECT 0.400 975.250 1399.390 976.070 ;
        RECT 0.400 975.230 1399.900 975.250 ;
        RECT 0.400 974.410 1399.390 975.230 ;
        RECT 0.400 974.390 1399.900 974.410 ;
        RECT 0.400 973.570 1399.390 974.390 ;
        RECT 0.400 973.550 1399.900 973.570 ;
        RECT 0.400 972.730 1399.390 973.550 ;
        RECT 0.400 972.710 1399.900 972.730 ;
        RECT 0.610 971.890 1399.390 972.710 ;
        RECT 0.400 971.870 1399.900 971.890 ;
        RECT 0.610 971.050 1399.390 971.870 ;
        RECT 0.400 971.030 1399.900 971.050 ;
        RECT 0.610 970.210 1399.390 971.030 ;
        RECT 0.400 968.510 1399.900 970.210 ;
        RECT 0.400 967.690 1399.390 968.510 ;
        RECT 0.400 965.990 1399.900 967.690 ;
        RECT 0.400 965.170 1399.390 965.990 ;
        RECT 0.400 959.270 1399.900 965.170 ;
        RECT 0.610 958.450 1399.900 959.270 ;
        RECT 0.400 953.390 1399.900 958.450 ;
        RECT 0.610 952.570 1399.900 953.390 ;
        RECT 0.400 952.550 1399.900 952.570 ;
        RECT 0.610 951.730 1399.900 952.550 ;
        RECT 0.400 947.510 1399.900 951.730 ;
        RECT 0.610 946.690 1399.900 947.510 ;
        RECT 0.400 939.110 1399.900 946.690 ;
        RECT 0.610 938.290 1399.900 939.110 ;
        RECT 0.400 50.390 1399.900 938.290 ;
        RECT 0.400 49.570 1399.390 50.390 ;
        RECT 0.400 49.550 1399.900 49.570 ;
        RECT 0.400 48.730 1399.390 49.550 ;
        RECT 0.400 48.710 1399.900 48.730 ;
        RECT 0.400 47.890 1399.390 48.710 ;
        RECT 0.400 31.070 1399.900 47.890 ;
        RECT 0.400 30.250 1399.390 31.070 ;
        RECT 0.400 30.230 1399.900 30.250 ;
        RECT 0.400 29.410 1399.390 30.230 ;
        RECT 0.400 29.390 1399.900 29.410 ;
        RECT 0.400 28.570 1399.390 29.390 ;
        RECT 0.400 28.550 1399.900 28.570 ;
        RECT 0.400 27.730 1399.390 28.550 ;
        RECT 0.400 27.710 1399.900 27.730 ;
        RECT 0.400 26.890 1399.390 27.710 ;
        RECT 0.400 26.870 1399.900 26.890 ;
        RECT 0.400 26.050 1399.390 26.870 ;
        RECT 0.400 26.030 1399.900 26.050 ;
        RECT 0.400 25.210 1399.390 26.030 ;
        RECT 0.400 25.190 1399.900 25.210 ;
        RECT 0.400 24.370 1399.390 25.190 ;
        RECT 0.400 24.350 1399.900 24.370 ;
        RECT 0.400 23.530 1399.390 24.350 ;
        RECT 0.400 23.510 1399.900 23.530 ;
        RECT 0.400 22.690 1399.390 23.510 ;
        RECT 0.400 0.320 1399.900 22.690 ;
      LAYER Metal4 ;
        RECT 6.135 14.975 1399.780 1399.165 ;
      LAYER Metal5 ;
        RECT 6.095 14.810 1389.265 1389.460 ;
      LAYER TopMetal1 ;
        RECT 180.940 34.880 243.420 1284.340 ;
        RECT 248.900 34.880 249.620 1284.340 ;
        RECT 255.100 34.880 319.020 1284.340 ;
        RECT 324.500 34.880 325.220 1284.340 ;
        RECT 330.700 34.880 394.620 1284.340 ;
        RECT 400.100 34.880 400.820 1284.340 ;
        RECT 406.300 34.880 470.220 1284.340 ;
        RECT 475.700 34.880 476.420 1284.340 ;
        RECT 481.900 34.880 545.820 1284.340 ;
        RECT 551.300 34.880 552.020 1284.340 ;
        RECT 557.500 34.880 621.420 1284.340 ;
        RECT 626.900 34.880 627.620 1284.340 ;
        RECT 633.100 34.880 697.020 1284.340 ;
        RECT 702.500 34.880 703.220 1284.340 ;
        RECT 708.700 34.880 772.620 1284.340 ;
        RECT 778.100 34.880 778.820 1284.340 ;
        RECT 784.300 34.880 848.220 1284.340 ;
        RECT 853.700 34.880 854.420 1284.340 ;
        RECT 859.900 34.880 923.820 1284.340 ;
        RECT 929.300 34.880 930.020 1284.340 ;
        RECT 935.500 34.880 999.420 1284.340 ;
        RECT 1004.900 34.880 1005.620 1284.340 ;
        RECT 1011.100 34.880 1075.020 1284.340 ;
        RECT 1080.500 34.880 1081.220 1284.340 ;
        RECT 1086.700 34.880 1150.620 1284.340 ;
        RECT 1156.100 34.880 1156.820 1284.340 ;
        RECT 1162.300 34.880 1226.220 1284.340 ;
        RECT 1231.700 34.880 1232.420 1284.340 ;
        RECT 1237.900 34.880 1301.820 1284.340 ;
        RECT 1307.300 34.880 1308.020 1284.340 ;
        RECT 1313.500 34.880 1377.300 1284.340 ;
      LAYER TopMetal2 ;
        RECT 589.880 945.220 1376.200 987.000 ;
        RECT 589.880 869.620 1376.200 932.820 ;
        RECT 589.880 794.020 1376.200 857.220 ;
        RECT 589.880 718.420 1376.200 781.620 ;
        RECT 589.880 642.820 1376.200 706.020 ;
        RECT 589.880 567.220 1376.200 630.420 ;
        RECT 589.880 491.620 1376.200 554.820 ;
        RECT 589.880 416.020 1376.200 479.220 ;
        RECT 589.880 340.420 1376.200 403.620 ;
        RECT 589.880 264.820 1376.200 328.020 ;
        RECT 589.880 189.220 1376.200 252.420 ;
        RECT 589.880 113.620 1376.200 176.820 ;
        RECT 589.880 81.000 1376.200 101.220 ;
  END
END svm_compute_core
END LIBRARY

